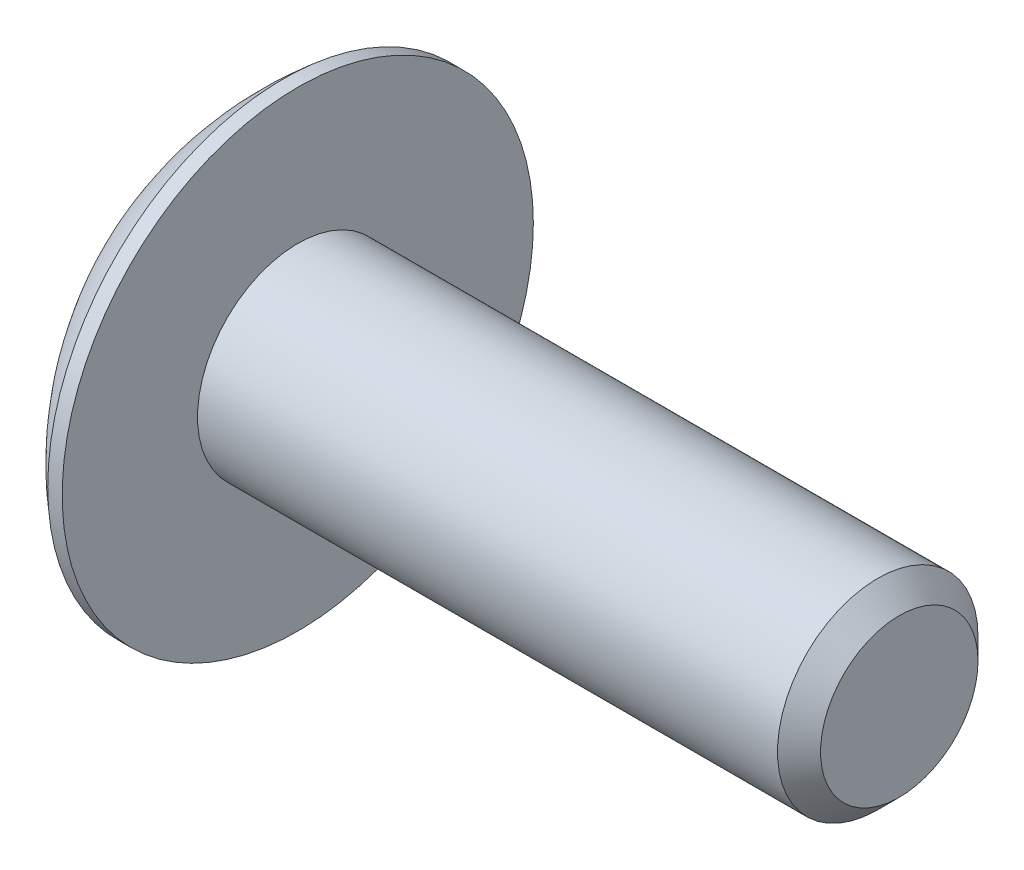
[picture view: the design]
ISO-10303-21;
HEADER;
FILE_DESCRIPTION(('STEP AP214'),'2;1');
FILE_NAME('part.step','',(''),(''),'','','');
FILE_SCHEMA(('AUTOMOTIVE_DESIGN { 1 0 10303 214 1 1 1 1 }'));
ENDSEC;
DATA;
#1=APPLICATION_CONTEXT('core data for automotive mechanical design processes');
#2=APPLICATION_PROTOCOL_DEFINITION('international standard','automotive_design',2000,#1);
#3=PRODUCT_CONTEXT('',#1,'mechanical');
#4=PRODUCT('Part','Part','',(#3));
#5=PRODUCT_RELATED_PRODUCT_CATEGORY('part','',(#4));
#6=PRODUCT_DEFINITION_FORMATION('','',#4);
#7=PRODUCT_DEFINITION_CONTEXT('part definition',#1,'design');
#8=PRODUCT_DEFINITION('design','',#6,#7);
#9=PRODUCT_DEFINITION_SHAPE('','',#8);
#10=(LENGTH_UNIT() NAMED_UNIT(*) SI_UNIT(.MILLI.,.METRE.));
#11=(NAMED_UNIT(*) PLANE_ANGLE_UNIT() SI_UNIT($,.RADIAN.));
#12=(NAMED_UNIT(*) SI_UNIT($,.STERADIAN.) SOLID_ANGLE_UNIT());
#13=UNCERTAINTY_MEASURE_WITH_UNIT(LENGTH_MEASURE(1.E-05),#10,'distance_accuracy_value','');
#14=(GEOMETRIC_REPRESENTATION_CONTEXT(3) GLOBAL_UNCERTAINTY_ASSIGNED_CONTEXT((#13)) GLOBAL_UNIT_ASSIGNED_CONTEXT((#10,
#11,#12)) REPRESENTATION_CONTEXT('',''));
#15=CARTESIAN_POINT('',(0.,0.,0.));
#16=DIRECTION('',(0.,0.,1.));
#17=DIRECTION('',(1.,0.,0.));
#18=AXIS2_PLACEMENT_3D('',#15,#16,#17);
#19=CARTESIAN_POINT('',(3.60000000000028,-1.29236898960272E-13,0.));
#20=DIRECTION('',(1.,0.,0.));
#21=DIRECTION('',(0.,1.,0.));
#22=AXIS2_PLACEMENT_3D('',#19,#20,#21);
#23=SPHERICAL_SURFACE('',#22,6.10000000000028);
#24=CARTESIAN_POINT('',(-0.288444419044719,0.,0.));
#25=DIRECTION('',(1.,0.,0.));
#26=DIRECTION('',(0.,0.,-1.));
#27=AXIS2_PLACEMENT_3D('',#24,#25,#26);
#28=CIRCLE('',#27,4.7);
#29=CARTESIAN_POINT('',(-0.288444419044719,0.,-4.7));
#30=VERTEX_POINT('',#29);
#31=EDGE_CURVE('E5',#30,#30,#28,.T.);
#32=ORIENTED_EDGE('',*,*,#31,.F.);
#33=EDGE_LOOP('',(#32));
#34=FACE_BOUND('',#33,.T.);
#35=CARTESIAN_POINT('',(-2.26198297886,0.626666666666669,1.5666666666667));
#36=CARTESIAN_POINT('',(-2.25890939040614,0.626667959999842,1.5781665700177));
#37=CARTESIAN_POINT('',(-2.25580100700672,0.626678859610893,1.58965715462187));
#38=CARTESIAN_POINT('',(-2.2494064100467,0.626709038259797,1.61301958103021));
#39=CARTESIAN_POINT('',(-2.24611777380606,0.626728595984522,1.62489075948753));
#40=CARTESIAN_POINT('',(-2.23937890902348,0.626764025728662,1.64893324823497));
#41=CARTESIAN_POINT('',(-2.23592671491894,0.626779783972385,1.66110400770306));
#42=CARTESIAN_POINT('',(-2.22887838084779,0.626801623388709,1.68566395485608));
#43=CARTESIAN_POINT('',(-2.22528074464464,0.626807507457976,1.698052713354));
#44=CARTESIAN_POINT('',(-2.2179609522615,0.626807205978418,1.72296657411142));
#45=CARTESIAN_POINT('',(-2.21423778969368,0.626800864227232,1.73549138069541));
#46=CARTESIAN_POINT('',(-2.20668807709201,0.626778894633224,1.76059497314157));
#47=CARTESIAN_POINT('',(-2.20286102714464,0.626763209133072,1.77317360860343));
#48=CARTESIAN_POINT('',(-2.19512675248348,0.626727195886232,1.7983024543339));
#49=CARTESIAN_POINT('',(-2.19121954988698,0.626706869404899,1.81085267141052));
#50=CARTESIAN_POINT('',(-2.18334912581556,0.626679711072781,1.8358420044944));
#51=CARTESIAN_POINT('',(-2.17938646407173,0.626672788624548,1.84828129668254));
#52=CARTESIAN_POINT('',(-2.17144141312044,0.626660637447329,1.87294574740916));
#53=CARTESIAN_POINT('',(-2.16746023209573,0.626655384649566,1.88517129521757));
#54=CARTESIAN_POINT('',(-2.15948191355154,0.626632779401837,1.90941347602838));
#55=CARTESIAN_POINT('',(-2.15548591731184,0.626615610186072,1.92143048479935));
#56=CARTESIAN_POINT('',(-2.1474531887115,0.626585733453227,1.94533538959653));
#57=CARTESIAN_POINT('',(-2.14341710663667,0.626572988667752,1.95722350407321));
#58=CARTESIAN_POINT('',(-2.13527849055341,0.62655544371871,1.98095075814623));
#59=CARTESIAN_POINT('',(-2.13117610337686,0.626550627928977,1.99278994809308));
#60=CARTESIAN_POINT('',(-2.12287713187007,0.626551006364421,2.01649936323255));
#61=CARTESIAN_POINT('',(-2.11868018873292,0.626556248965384,2.02836946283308));
#62=CARTESIAN_POINT('',(-2.1101626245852,0.626574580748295,2.05222057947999));
#63=CARTESIAN_POINT('',(-2.1058411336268,0.62658776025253,2.06420128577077));
#64=CARTESIAN_POINT('',(-2.0970431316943,0.626616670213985,2.08835324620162));
#65=CARTESIAN_POINT('',(-2.09256523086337,0.626632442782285,2.10052399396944));
#66=CARTESIAN_POINT('',(-2.08342122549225,0.626657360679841,2.12513535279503));
#67=CARTESIAN_POINT('',(-2.07875319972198,0.62666633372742,2.13757525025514));
#68=CARTESIAN_POINT('',(-2.07404519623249,0.62666666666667,2.15));
#69=B_SPLINE_CURVE_WITH_KNOTS('',3,(#35,#36,#37,#38,#39,#40,#41,#42,#43,#44,#45,#46,#47,#48,#49,
#50,#51,#52,#53,#54,#55,#56,#57,#58,#59,#60,#61,#62,#63,#64,#65,#66,#67,#68),.UNSPECIFIED.,.F.,
.F.,(4,2,2,2,2,2,2,2,2,2,2,2,2,2,2,2,4),(0.,0.0357105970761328,0.0726652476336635,
0.110617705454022,0.149319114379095,0.188518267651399,0.227961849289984,0.267394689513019,
0.306560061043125,0.345132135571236,0.383123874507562,0.420787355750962,0.45837652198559,
0.496146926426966,0.534355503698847,0.573260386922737,0.613120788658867),.UNSPECIFIED.);
#70=CARTESIAN_POINT('',(-2.26198297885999,0.62666666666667,1.5666666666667));
#71=VERTEX_POINT('',#70);
#72=CARTESIAN_POINT('',(-2.07404519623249,0.62666666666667,2.15));
#73=VERTEX_POINT('',#72);
#74=EDGE_CURVE('E8',#71,#73,#69,.T.);
#75=ORIENTED_EDGE('',*,*,#74,.T.);
#76=CARTESIAN_POINT('',(-2.07404519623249,0.626666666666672,2.15));
#77=CARTESIAN_POINT('',(-2.07704980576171,0.599465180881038,2.14999909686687));
#78=CARTESIAN_POINT('',(-2.07986503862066,0.57224267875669,2.14998150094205));
#79=CARTESIAN_POINT('',(-2.08506116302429,0.51825623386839,2.14993301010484));
#80=CARTESIAN_POINT('',(-2.08744902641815,0.491492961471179,2.14990236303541));
#81=CARTESIAN_POINT('',(-2.09181031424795,0.438353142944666,2.14984684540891));
#82=CARTESIAN_POINT('',(-2.09378962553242,0.411977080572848,2.14982189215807));
#83=CARTESIAN_POINT('',(-2.09735237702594,0.359540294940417,2.14978796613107));
#84=CARTESIAN_POINT('',(-2.09894059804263,0.333479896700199,2.14977879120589));
#85=CARTESIAN_POINT('',(-2.1017378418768,0.281603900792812,2.14977968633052));
#86=CARTESIAN_POINT('',(-2.10295054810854,0.255788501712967,2.1497895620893));
#87=CARTESIAN_POINT('',(-2.10501180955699,0.204333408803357,2.14982468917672));
#88=CARTESIAN_POINT('',(-2.10586297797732,0.178693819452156,2.14984982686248));
#89=CARTESIAN_POINT('',(-2.10721463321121,0.127523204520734,2.14990488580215));
#90=CARTESIAN_POINT('',(-2.10771671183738,0.101992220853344,2.14993478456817));
#91=CARTESIAN_POINT('',(-2.10838218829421,0.0509741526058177,2.14998233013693));
#92=CARTESIAN_POINT('',(-2.10854622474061,0.025487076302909,2.15));
#93=CARTESIAN_POINT('',(-2.10854622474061,-0.0254870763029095,2.15));
#94=CARTESIAN_POINT('',(-2.10838218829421,-0.0509741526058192,2.14998233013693));
#95=CARTESIAN_POINT('',(-2.10771671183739,-0.101992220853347,2.14993478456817));
#96=CARTESIAN_POINT('',(-2.10721463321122,-0.127523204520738,2.14990488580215));
#97=CARTESIAN_POINT('',(-2.10586297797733,-0.17869381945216,2.14984982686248));
#98=CARTESIAN_POINT('',(-2.10501180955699,-0.204333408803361,2.14982468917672));
#99=CARTESIAN_POINT('',(-2.10295054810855,-0.255788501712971,2.1497895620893));
#100=CARTESIAN_POINT('',(-2.10173784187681,-0.281603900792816,2.14977968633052));
#101=CARTESIAN_POINT('',(-2.09894059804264,-0.333479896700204,2.14977879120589));
#102=CARTESIAN_POINT('',(-2.09735237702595,-0.359540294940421,2.14978796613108));
#103=CARTESIAN_POINT('',(-2.09378962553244,-0.411977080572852,2.14982189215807));
#104=CARTESIAN_POINT('',(-2.09181031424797,-0.438353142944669,2.14984684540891));
#105=CARTESIAN_POINT('',(-2.08744902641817,-0.491492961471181,2.14990236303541));
#106=CARTESIAN_POINT('',(-2.08506116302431,-0.518256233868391,2.14993301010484));
#107=CARTESIAN_POINT('',(-2.07986503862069,-0.57224267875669,2.14998150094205));
#108=CARTESIAN_POINT('',(-2.07704980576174,-0.599465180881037,2.14999909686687));
#109=CARTESIAN_POINT('',(-2.07404519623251,-0.626666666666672,2.15));
#110=B_SPLINE_CURVE_WITH_KNOTS('',3,(#76,#77,#78,#79,#80,#81,#82,#83,#84,#85,#86,#87,#88,#89,
#90,#91,#92,#93,#94,#95,#96,#97,#98,#99,#100,#101,#102,#103,#104,#105,#106,#107,#108,#109),
.UNSPECIFIED.,.F.,.F.,(4,2,2,2,2,2,2,2,2,2,2,2,2,2,2,2,4),(0.,0.0821002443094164,
0.162706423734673,0.242054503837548,0.320378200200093,0.397907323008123,0.47486611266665,
0.551471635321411,0.62793230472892,0.704392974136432,0.780998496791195,0.857957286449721,
0.935486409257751,1.0138101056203,1.09315818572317,1.17376436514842,1.25586460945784),.UNSPECIFIED.);
#111=CARTESIAN_POINT('',(-2.07404519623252,-0.62666666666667,2.15));
#112=VERTEX_POINT('',#111);
#113=EDGE_CURVE('E23',#73,#112,#110,.T.);
#114=ORIENTED_EDGE('',*,*,#113,.T.);
#115=CARTESIAN_POINT('',(-2.07404519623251,-0.626666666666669,2.15));
#116=CARTESIAN_POINT('',(-2.07875319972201,-0.62666633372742,2.13757525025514));
#117=CARTESIAN_POINT('',(-2.08342122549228,-0.626657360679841,2.12513535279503));
#118=CARTESIAN_POINT('',(-2.0925652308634,-0.626632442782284,2.10052399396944));
#119=CARTESIAN_POINT('',(-2.09704313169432,-0.626616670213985,2.08835324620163));
#120=CARTESIAN_POINT('',(-2.10584113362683,-0.626587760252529,2.06420128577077));
#121=CARTESIAN_POINT('',(-2.11016262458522,-0.626574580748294,2.05222057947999));
#122=CARTESIAN_POINT('',(-2.11868018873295,-0.626556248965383,2.02836946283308));
#123=CARTESIAN_POINT('',(-2.1228771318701,-0.62655100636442,2.01649936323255));
#124=CARTESIAN_POINT('',(-2.13117610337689,-0.626550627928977,1.99278994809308));
#125=CARTESIAN_POINT('',(-2.13527849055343,-0.62655544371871,1.98095075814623));
#126=CARTESIAN_POINT('',(-2.1434171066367,-0.626572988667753,1.95722350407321));
#127=CARTESIAN_POINT('',(-2.14745318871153,-0.626585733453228,1.94533538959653));
#128=CARTESIAN_POINT('',(-2.15548591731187,-0.626615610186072,1.92143048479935));
#129=CARTESIAN_POINT('',(-2.15948191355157,-0.626632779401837,1.90941347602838));
#130=CARTESIAN_POINT('',(-2.16746023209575,-0.626655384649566,1.88517129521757));
#131=CARTESIAN_POINT('',(-2.17144141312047,-0.626660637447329,1.87294574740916));
#132=CARTESIAN_POINT('',(-2.17938646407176,-0.626672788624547,1.84828129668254));
#133=CARTESIAN_POINT('',(-2.18334912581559,-0.626679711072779,1.8358420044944));
#134=CARTESIAN_POINT('',(-2.19121954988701,-0.626706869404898,1.81085267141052));
#135=CARTESIAN_POINT('',(-2.1951267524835,-0.626727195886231,1.7983024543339));
#136=CARTESIAN_POINT('',(-2.20286102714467,-0.626763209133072,1.77317360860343));
#137=CARTESIAN_POINT('',(-2.20668807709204,-0.626778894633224,1.76059497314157));
#138=CARTESIAN_POINT('',(-2.21423778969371,-0.626800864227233,1.73549138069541));
#139=CARTESIAN_POINT('',(-2.21796095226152,-0.626807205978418,1.72296657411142));
#140=CARTESIAN_POINT('',(-2.22528074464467,-0.626807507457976,1.69805271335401));
#141=CARTESIAN_POINT('',(-2.22887838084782,-0.626801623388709,1.68566395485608));
#142=CARTESIAN_POINT('',(-2.23592671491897,-0.626779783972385,1.66110400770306));
#143=CARTESIAN_POINT('',(-2.2393789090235,-0.626764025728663,1.64893324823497));
#144=CARTESIAN_POINT('',(-2.24611777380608,-0.626728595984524,1.62489075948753));
#145=CARTESIAN_POINT('',(-2.24940641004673,-0.626709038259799,1.61301958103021));
#146=CARTESIAN_POINT('',(-2.25580100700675,-0.626678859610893,1.58965715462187));
#147=CARTESIAN_POINT('',(-2.25890939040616,-0.626667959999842,1.5781665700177));
#148=CARTESIAN_POINT('',(-2.26198297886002,-0.62666666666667,1.5666666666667));
#149=B_SPLINE_CURVE_WITH_KNOTS('',3,(#115,#116,#117,#118,#119,#120,#121,#122,#123,#124,#125,
#126,#127,#128,#129,#130,#131,#132,#133,#134,#135,#136,#137,#138,#139,#140,#141,#142,#143,#144,
#145,#146,#147,#148),.UNSPECIFIED.,.F.,.F.,(4,2,2,2,2,2,2,2,2,2,2,2,2,2,2,2,4),(0.,
0.03986040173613,0.0787652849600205,0.116973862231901,0.154744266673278,0.192333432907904,
0.229996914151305,0.267988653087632,0.306560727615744,0.345726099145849,0.385158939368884,
0.424602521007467,0.463801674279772,0.502503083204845,0.540455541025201,0.577410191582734,
0.613120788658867),.UNSPECIFIED.);
#150=CARTESIAN_POINT('',(-2.26198297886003,-0.62666666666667,1.5666666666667));
#151=VERTEX_POINT('',#150);
#152=EDGE_CURVE('E37',#112,#151,#149,.T.);
#153=ORIENTED_EDGE('',*,*,#152,.T.);
#154=CARTESIAN_POINT('',(-2.26198297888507,-1.56666666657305,0.626666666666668));
#155=CARTESIAN_POINT('',(-2.26520019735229,-1.55462889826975,0.626666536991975));
#156=CARTESIAN_POINT('',(-2.26835697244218,-1.54257482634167,0.626897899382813));
#157=CARTESIAN_POINT('',(-2.27454382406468,-1.51845661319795,0.627826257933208));
#158=CARTESIAN_POINT('',(-2.27757394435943,-1.50639247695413,0.628523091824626));
#159=CARTESIAN_POINT('',(-2.28350314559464,-1.4822714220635,0.630384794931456));
#160=CARTESIAN_POINT('',(-2.28640226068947,-1.47021450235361,0.631549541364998));
#161=CARTESIAN_POINT('',(-2.29206511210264,-1.44612548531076,0.634348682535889));
#162=CARTESIAN_POINT('',(-2.29482887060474,-1.43409338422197,0.635983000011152));
#163=CARTESIAN_POINT('',(-2.30021667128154,-1.41007177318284,0.639722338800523));
#164=CARTESIAN_POINT('',(-2.30284072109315,-1.39808226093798,0.641827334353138));
#165=CARTESIAN_POINT('',(-2.30794477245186,-1.37416378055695,0.64650844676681));
#166=CARTESIAN_POINT('',(-2.31042476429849,-1.36223481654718,0.649084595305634));
#167=CARTESIAN_POINT('',(-2.31523635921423,-1.33845553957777,0.654707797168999));
#168=CARTESIAN_POINT('',(-2.31756793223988,-1.32660524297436,0.657754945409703));
#169=CARTESIAN_POINT('',(-2.32207839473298,-1.30300155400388,0.664319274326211));
#170=CARTESIAN_POINT('',(-2.3242572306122,-1.2912481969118,0.667836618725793));
#171=CARTESIAN_POINT('',(-2.32845717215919,-1.26786005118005,0.675338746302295));
#172=CARTESIAN_POINT('',(-2.33047824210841,-1.2562252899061,0.679323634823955));
#173=CARTESIAN_POINT('',(-2.33435678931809,-1.23310506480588,0.687753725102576));
#174=CARTESIAN_POINT('',(-2.33621437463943,-1.22161950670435,0.692198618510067));
#175=CARTESIAN_POINT('',(-2.33976346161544,-1.19881668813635,0.701543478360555));
#176=CARTESIAN_POINT('',(-2.34145505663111,-1.18749933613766,0.706443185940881));
#177=CARTESIAN_POINT('',(-2.34466971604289,-1.16505055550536,0.716692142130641));
#178=CARTESIAN_POINT('',(-2.34619283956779,-1.15391906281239,0.722041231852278));
#179=CARTESIAN_POINT('',(-2.34906816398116,-1.13185950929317,0.733182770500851));
#180=CARTESIAN_POINT('',(-2.35042038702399,-1.12093142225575,0.738975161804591));
#181=CARTESIAN_POINT('',(-2.35295150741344,-1.09929603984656,0.750996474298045));
#182=CARTESIAN_POINT('',(-2.35413038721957,-1.08858876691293,0.757225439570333));
#183=CARTESIAN_POINT('',(-2.35631242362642,-1.06741220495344,0.770112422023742));
#184=CARTESIAN_POINT('',(-2.3573155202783,-1.05694299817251,0.776770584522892));
#185=CARTESIAN_POINT('',(-2.35914359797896,-1.03625957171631,0.790507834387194));
#186=CARTESIAN_POINT('',(-2.35996847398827,-1.02604550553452,0.797587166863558));
#187=CARTESIAN_POINT('',(-2.3614376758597,-1.00588959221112,0.81215766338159));
#188=CARTESIAN_POINT('',(-2.36208185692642,-0.995947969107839,0.819649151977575));
#189=CARTESIAN_POINT('',(-2.36318662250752,-0.976365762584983,0.835024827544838));
#190=CARTESIAN_POINT('',(-2.36364724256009,-0.96672512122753,0.842908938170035));
#191=CARTESIAN_POINT('',(-2.36438476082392,-0.947765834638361,0.859053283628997));
#192=CARTESIAN_POINT('',(-2.36466175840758,-0.938447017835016,0.86731331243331));
#193=CARTESIAN_POINT('',(-2.36503230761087,-0.92014596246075,0.884196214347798));
#194=CARTESIAN_POINT('',(-2.3651259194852,-0.911163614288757,0.892818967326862));
#195=CARTESIAN_POINT('',(-2.36513000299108,-0.893549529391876,0.910413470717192));
#196=CARTESIAN_POINT('',(-2.36504049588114,-0.88491775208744,0.919385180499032));
#197=CARTESIAN_POINT('',(-2.36467864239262,-0.868018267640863,0.93766320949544));
#198=CARTESIAN_POINT('',(-2.36440627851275,-0.859750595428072,0.946969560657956));
#199=CARTESIAN_POINT('',(-2.36367900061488,-0.843592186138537,0.96590196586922));
#200=CARTESIAN_POINT('',(-2.36322403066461,-0.835701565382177,0.975528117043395));
#201=CARTESIAN_POINT('',(-2.36213188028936,-0.820309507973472,0.995084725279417));
#202=CARTESIAN_POINT('',(-2.36149460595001,-0.812808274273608,1.0050153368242));
#203=CARTESIAN_POINT('',(-2.36003800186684,-0.798206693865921,1.02516488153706));
#204=CARTESIAN_POINT('',(-2.3592185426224,-0.791106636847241,1.0353840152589));
#205=CARTESIAN_POINT('',(-2.35739943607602,-0.777325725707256,1.05608322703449));
#206=CARTESIAN_POINT('',(-2.35639981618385,-0.770644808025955,1.06656326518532));
#207=CARTESIAN_POINT('',(-2.35422388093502,-0.757715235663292,1.08775998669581));
#208=CARTESIAN_POINT('',(-2.35304767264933,-0.751466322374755,1.09847652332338));
#209=CARTESIAN_POINT('',(-2.35052125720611,-0.73940756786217,1.12012899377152));
#210=CARTESIAN_POINT('',(-2.34917110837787,-0.733597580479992,1.13106485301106));
#211=CARTESIAN_POINT('',(-2.34629960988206,-0.722422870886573,1.15313863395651));
#212=CARTESIAN_POINT('',(-2.34477827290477,-0.71705811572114,1.16427654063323));
#213=CARTESIAN_POINT('',(-2.34156716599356,-0.706779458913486,1.18673700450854));
#214=CARTESIAN_POINT('',(-2.33987736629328,-0.70186563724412,1.19805959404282));
#215=CARTESIAN_POINT('',(-2.33633210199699,-0.692493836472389,1.22087195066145));
#216=CARTESIAN_POINT('',(-2.3344765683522,-0.688036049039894,1.23236178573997));
#217=CARTESIAN_POINT('',(-2.33060261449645,-0.679580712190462,1.25549111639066));
#218=CARTESIAN_POINT('',(-2.32858408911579,-0.675583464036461,1.26713070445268));
#219=CARTESIAN_POINT('',(-2.32438689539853,-0.668053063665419,1.29054183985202));
#220=CARTESIAN_POINT('',(-2.32220809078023,-0.664520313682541,1.30231349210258));
#221=CARTESIAN_POINT('',(-2.31769491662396,-0.657924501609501,1.32596264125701));
#222=CARTESIAN_POINT('',(-2.31536049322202,-0.654861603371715,1.33784017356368));
#223=CARTESIAN_POINT('',(-2.31054161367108,-0.649208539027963,1.36167732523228));
#224=CARTESIAN_POINT('',(-2.30805715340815,-0.646618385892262,1.37363694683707));
#225=CARTESIAN_POINT('',(-2.30294285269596,-0.641911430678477,1.39761906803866));
#226=CARTESIAN_POINT('',(-2.30031300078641,-0.639794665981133,1.40964157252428));
#227=CARTESIAN_POINT('',(-2.29491260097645,-0.636034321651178,1.43373037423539));
#228=CARTESIAN_POINT('',(-2.29214203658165,-0.634390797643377,1.44579667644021));
#229=CARTESIAN_POINT('',(-2.28646488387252,-0.631575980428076,1.46995414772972));
#230=CARTESIAN_POINT('',(-2.2835582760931,-0.630404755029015,1.48204532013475));
#231=CARTESIAN_POINT('',(-2.27761371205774,-0.62853287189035,1.50623376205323));
#232=CARTESIAN_POINT('',(-2.27457573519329,-0.627832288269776,1.51833103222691));
#233=CARTESIAN_POINT('',(-2.26837309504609,-0.62689908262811,1.54251322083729));
#234=CARTESIAN_POINT('',(-2.26520841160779,-0.626666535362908,1.55459813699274));
#235=CARTESIAN_POINT('',(-2.2619829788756,-0.626666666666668,1.5666666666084));
#236=B_SPLINE_CURVE_WITH_KNOTS('',3,(#154,#155,#156,#157,#158,#159,#160,#161,#162,#163,#164,
#165,#166,#167,#168,#169,#170,#171,#172,#173,#174,#175,#176,#177,#178,#179,#180,#181,#182,#183,
#184,#185,#186,#187,#188,#189,#190,#191,#192,#193,#194,#195,#196,#197,#198,#199,#200,#201,#202,
#203,#204,#205,#206,#207,#208,#209,#210,#211,#212,#213,#214,#215,#216,#217,#218,#219,#220,#221,
#222,#223,#224,#225,#226,#227,#228,#229,#230,#231,#232,#233,#234,#235),.UNSPECIFIED.,.F.,.F.,(4,
2,2,2,2,2,2,2,2,2,2,2,2,2,2,2,2,2,2,2,2,2,2,2,2,2,2,2,2,2,2,2,2,2,2,2,2,2,2,2,4),(0.,
0.0373787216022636,0.0747444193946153,0.112100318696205,0.1494500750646,0.186797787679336,
0.224148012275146,0.261505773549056,0.29887657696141,0.336255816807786,0.373610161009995,
0.410943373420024,0.448263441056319,0.485578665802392,0.522897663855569,0.560229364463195,
0.597583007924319,0.634966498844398,0.672342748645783,0.709698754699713,0.747042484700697,
0.78438187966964,0.821724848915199,0.859079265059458,0.896452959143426,0.933853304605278,
0.971247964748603,1.00862004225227,1.04597961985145,1.08333642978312,1.12069985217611,
1.15807891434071,1.19548229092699,1.23291784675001,1.27036642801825,1.30781603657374,
1.34526860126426,1.38272556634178,1.42018790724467,1.45765614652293,1.49513036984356),.UNSPECIFIED.);
#237=CARTESIAN_POINT('',(-2.26198297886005,-1.5666666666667,0.62666666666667));
#238=VERTEX_POINT('',#237);
#239=EDGE_CURVE('E51',#238,#151,#236,.T.);
#240=ORIENTED_EDGE('',*,*,#239,.F.);
#241=CARTESIAN_POINT('',(-2.26198297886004,-1.5666666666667,0.626666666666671));
#242=CARTESIAN_POINT('',(-2.25890939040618,-1.5781665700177,0.626667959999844));
#243=CARTESIAN_POINT('',(-2.25580100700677,-1.58965715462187,0.626678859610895));
#244=CARTESIAN_POINT('',(-2.24940641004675,-1.61301958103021,0.626709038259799));
#245=CARTESIAN_POINT('',(-2.24611777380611,-1.62489075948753,0.626728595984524));
#246=CARTESIAN_POINT('',(-2.23937890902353,-1.64893324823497,0.626764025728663));
#247=CARTESIAN_POINT('',(-2.23592671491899,-1.66110400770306,0.626779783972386));
#248=CARTESIAN_POINT('',(-2.22887838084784,-1.68566395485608,0.62680162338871));
#249=CARTESIAN_POINT('',(-2.22528074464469,-1.698052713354,0.626807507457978));
#250=CARTESIAN_POINT('',(-2.21796095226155,-1.72296657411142,0.626807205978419));
#251=CARTESIAN_POINT('',(-2.21423778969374,-1.73549138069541,0.626800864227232));
#252=CARTESIAN_POINT('',(-2.20668807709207,-1.76059497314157,0.626778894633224));
#253=CARTESIAN_POINT('',(-2.20286102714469,-1.77317360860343,0.626763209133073));
#254=CARTESIAN_POINT('',(-2.19512675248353,-1.7983024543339,0.626727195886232));
#255=CARTESIAN_POINT('',(-2.19121954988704,-1.81085267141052,0.626706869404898));
#256=CARTESIAN_POINT('',(-2.18334912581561,-1.8358420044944,0.626679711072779));
#257=CARTESIAN_POINT('',(-2.17938646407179,-1.84828129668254,0.626672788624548));
#258=CARTESIAN_POINT('',(-2.1714414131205,-1.87294574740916,0.62666063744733));
#259=CARTESIAN_POINT('',(-2.16746023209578,-1.88517129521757,0.626655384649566));
#260=CARTESIAN_POINT('',(-2.1594819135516,-1.90941347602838,0.626632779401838));
#261=CARTESIAN_POINT('',(-2.1554859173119,-1.92143048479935,0.626615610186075));
#262=CARTESIAN_POINT('',(-2.14745318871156,-1.94533538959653,0.62658573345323));
#263=CARTESIAN_POINT('',(-2.14341710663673,-1.95722350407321,0.626572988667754));
#264=CARTESIAN_POINT('',(-2.13527849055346,-1.98095075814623,0.62655544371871));
#265=CARTESIAN_POINT('',(-2.13117610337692,-1.99278994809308,0.626550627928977));
#266=CARTESIAN_POINT('',(-2.12287713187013,-2.01649936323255,0.626551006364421));
#267=CARTESIAN_POINT('',(-2.11868018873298,-2.02836946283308,0.626556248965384));
#268=CARTESIAN_POINT('',(-2.11016262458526,-2.05222057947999,0.626574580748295));
#269=CARTESIAN_POINT('',(-2.10584113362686,-2.06420128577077,0.62658776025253));
#270=CARTESIAN_POINT('',(-2.09704313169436,-2.08835324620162,0.626616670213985));
#271=CARTESIAN_POINT('',(-2.09256523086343,-2.10052399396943,0.626632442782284));
#272=CARTESIAN_POINT('',(-2.08342122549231,-2.12513535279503,0.626657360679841));
#273=CARTESIAN_POINT('',(-2.07875319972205,-2.13757525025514,0.62666633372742));
#274=CARTESIAN_POINT('',(-2.07404519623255,-2.15,0.62666666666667));
#275=B_SPLINE_CURVE_WITH_KNOTS('',3,(#241,#242,#243,#244,#245,#246,#247,#248,#249,#250,#251,
#252,#253,#254,#255,#256,#257,#258,#259,#260,#261,#262,#263,#264,#265,#266,#267,#268,#269,#270,
#271,#272,#273,#274),.UNSPECIFIED.,.F.,.F.,(4,2,2,2,2,2,2,2,2,2,2,2,2,2,2,2,4),(0.,
0.0357105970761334,0.0726652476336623,0.110617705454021,0.149319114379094,0.188518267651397,
0.227961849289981,0.267394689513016,0.306560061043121,0.345132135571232,0.383123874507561,
0.420787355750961,0.458376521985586,0.49614692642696,0.534355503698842,0.573260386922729,
0.613120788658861),.UNSPECIFIED.);
#276=CARTESIAN_POINT('',(-2.07404519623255,-2.15,0.62666666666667));
#277=VERTEX_POINT('',#276);
#278=EDGE_CURVE('E65',#238,#277,#275,.T.);
#279=ORIENTED_EDGE('',*,*,#278,.T.);
#280=CARTESIAN_POINT('',(-2.07404519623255,-2.15,0.626666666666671));
#281=CARTESIAN_POINT('',(-2.07704980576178,-2.14999909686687,0.599465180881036));
#282=CARTESIAN_POINT('',(-2.07986503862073,-2.14998150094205,0.572242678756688));
#283=CARTESIAN_POINT('',(-2.08506116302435,-2.14993301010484,0.518256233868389));
#284=CARTESIAN_POINT('',(-2.08744902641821,-2.14990236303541,0.49149296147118));
#285=CARTESIAN_POINT('',(-2.09181031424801,-2.14984684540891,0.438353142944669));
#286=CARTESIAN_POINT('',(-2.09378962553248,-2.14982189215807,0.411977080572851));
#287=CARTESIAN_POINT('',(-2.09735237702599,-2.14978796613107,0.359540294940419));
#288=CARTESIAN_POINT('',(-2.09894059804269,-2.14977879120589,0.3334798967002));
#289=CARTESIAN_POINT('',(-2.10173784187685,-2.14977968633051,0.281603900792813));
#290=CARTESIAN_POINT('',(-2.10295054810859,-2.1497895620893,0.25578850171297));
#291=CARTESIAN_POINT('',(-2.10501180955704,-2.14982468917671,0.204333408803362));
#292=CARTESIAN_POINT('',(-2.10586297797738,-2.14984982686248,0.178693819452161));
#293=CARTESIAN_POINT('',(-2.10721463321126,-2.14990488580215,0.127523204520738));
#294=CARTESIAN_POINT('',(-2.10771671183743,-2.14993478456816,0.101992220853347));
#295=CARTESIAN_POINT('',(-2.10838218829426,-2.14998233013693,0.0509741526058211));
#296=CARTESIAN_POINT('',(-2.10854622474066,-2.15,0.0254870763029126));
#297=CARTESIAN_POINT('',(-2.10854622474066,-2.15,-0.0254870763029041));
#298=CARTESIAN_POINT('',(-2.10838218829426,-2.14998233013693,-0.0509741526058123));
#299=CARTESIAN_POINT('',(-2.10771671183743,-2.14993478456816,-0.101992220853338));
#300=CARTESIAN_POINT('',(-2.10721463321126,-2.14990488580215,-0.127523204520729));
#301=CARTESIAN_POINT('',(-2.10586297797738,-2.14984982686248,-0.17869381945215));
#302=CARTESIAN_POINT('',(-2.10501180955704,-2.14982468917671,-0.204333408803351));
#303=CARTESIAN_POINT('',(-2.10295054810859,-2.1497895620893,-0.25578850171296));
#304=CARTESIAN_POINT('',(-2.10173784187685,-2.14977968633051,-0.281603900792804));
#305=CARTESIAN_POINT('',(-2.09894059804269,-2.14977879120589,-0.333479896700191));
#306=CARTESIAN_POINT('',(-2.097352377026,-2.14978796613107,-0.359540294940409));
#307=CARTESIAN_POINT('',(-2.09378962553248,-2.14982189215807,-0.41197708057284));
#308=CARTESIAN_POINT('',(-2.09181031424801,-2.1498468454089,-0.438353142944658));
#309=CARTESIAN_POINT('',(-2.08744902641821,-2.1499023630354,-0.491492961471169));
#310=CARTESIAN_POINT('',(-2.08506116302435,-2.14993301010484,-0.518256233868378));
#311=CARTESIAN_POINT('',(-2.07986503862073,-2.14998150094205,-0.572242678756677));
#312=CARTESIAN_POINT('',(-2.07704980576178,-2.14999909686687,-0.599465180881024));
#313=CARTESIAN_POINT('',(-2.07404519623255,-2.15,-0.626666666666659));
#314=B_SPLINE_CURVE_WITH_KNOTS('',3,(#280,#281,#282,#283,#284,#285,#286,#287,#288,#289,#290,
#291,#292,#293,#294,#295,#296,#297,#298,#299,#300,#301,#302,#303,#304,#305,#306,#307,#308,#309,
#310,#311,#312,#313),.UNSPECIFIED.,.F.,.F.,(4,2,2,2,2,2,2,2,2,2,2,2,2,2,2,2,4),(0.,
0.082100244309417,0.162706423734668,0.242054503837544,0.320378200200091,0.397907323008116,
0.474866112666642,0.551471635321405,0.627932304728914,0.704392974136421,0.780998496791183,
0.857957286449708,0.935486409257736,1.01381010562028,1.09315818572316,1.17376436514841,
1.25586460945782),.UNSPECIFIED.);
#315=CARTESIAN_POINT('',(-2.07404519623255,-2.15,-0.62666666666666));
#316=VERTEX_POINT('',#315);
#317=EDGE_CURVE('E79',#277,#316,#314,.T.);
#318=ORIENTED_EDGE('',*,*,#317,.T.);
#319=CARTESIAN_POINT('',(-2.07404519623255,-2.15,-0.626666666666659));
#320=CARTESIAN_POINT('',(-2.07875319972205,-2.13757525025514,-0.626666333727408));
#321=CARTESIAN_POINT('',(-2.08342122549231,-2.12513535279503,-0.626657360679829));
#322=CARTESIAN_POINT('',(-2.09256523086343,-2.10052399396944,-0.626632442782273));
#323=CARTESIAN_POINT('',(-2.09704313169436,-2.08835324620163,-0.626616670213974));
#324=CARTESIAN_POINT('',(-2.10584113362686,-2.06420128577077,-0.626587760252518));
#325=CARTESIAN_POINT('',(-2.11016262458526,-2.05222057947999,-0.626574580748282));
#326=CARTESIAN_POINT('',(-2.11868018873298,-2.02836946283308,-0.626556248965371));
#327=CARTESIAN_POINT('',(-2.12287713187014,-2.01649936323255,-0.626551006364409));
#328=CARTESIAN_POINT('',(-2.13117610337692,-1.99278994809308,-0.626550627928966));
#329=CARTESIAN_POINT('',(-2.13527849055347,-1.98095075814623,-0.626555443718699));
#330=CARTESIAN_POINT('',(-2.14341710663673,-1.95722350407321,-0.626572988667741));
#331=CARTESIAN_POINT('',(-2.14745318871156,-1.94533538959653,-0.626585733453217));
#332=CARTESIAN_POINT('',(-2.1554859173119,-1.92143048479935,-0.626615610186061));
#333=CARTESIAN_POINT('',(-2.1594819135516,-1.90941347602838,-0.626632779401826));
#334=CARTESIAN_POINT('',(-2.16746023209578,-1.88517129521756,-0.626655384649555));
#335=CARTESIAN_POINT('',(-2.1714414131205,-1.87294574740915,-0.626660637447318));
#336=CARTESIAN_POINT('',(-2.17938646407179,-1.84828129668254,-0.626672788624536));
#337=CARTESIAN_POINT('',(-2.18334912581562,-1.83584200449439,-0.626679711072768));
#338=CARTESIAN_POINT('',(-2.19121954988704,-1.81085267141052,-0.626706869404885));
#339=CARTESIAN_POINT('',(-2.19512675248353,-1.79830245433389,-0.626727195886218));
#340=CARTESIAN_POINT('',(-2.20286102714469,-1.77317360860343,-0.62676320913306));
#341=CARTESIAN_POINT('',(-2.20668807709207,-1.76059497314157,-0.626778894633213));
#342=CARTESIAN_POINT('',(-2.21423778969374,-1.7354913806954,-0.626800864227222));
#343=CARTESIAN_POINT('',(-2.21796095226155,-1.72296657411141,-0.626807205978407));
#344=CARTESIAN_POINT('',(-2.2252807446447,-1.698052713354,-0.626807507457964));
#345=CARTESIAN_POINT('',(-2.22887838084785,-1.68566395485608,-0.626801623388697));
#346=CARTESIAN_POINT('',(-2.23592671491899,-1.66110400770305,-0.626779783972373));
#347=CARTESIAN_POINT('',(-2.23937890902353,-1.64893324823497,-0.626764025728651));
#348=CARTESIAN_POINT('',(-2.24611777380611,-1.62489075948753,-0.626728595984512));
#349=CARTESIAN_POINT('',(-2.24940641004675,-1.61301958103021,-0.626709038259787));
#350=CARTESIAN_POINT('',(-2.25580100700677,-1.58965715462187,-0.626678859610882));
#351=CARTESIAN_POINT('',(-2.25890939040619,-1.5781665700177,-0.626667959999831));
#352=CARTESIAN_POINT('',(-2.26198297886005,-1.5666666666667,-0.626666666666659));
#353=B_SPLINE_CURVE_WITH_KNOTS('',3,(#319,#320,#321,#322,#323,#324,#325,#326,#327,#328,#329,
#330,#331,#332,#333,#334,#335,#336,#337,#338,#339,#340,#341,#342,#343,#344,#345,#346,#347,#348,
#349,#350,#351,#352),.UNSPECIFIED.,.F.,.F.,(4,2,2,2,2,2,2,2,2,2,2,2,2,2,2,2,4),(0.,
0.0398604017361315,0.0787652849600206,0.116973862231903,0.154744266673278,0.192333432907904,
0.229996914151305,0.267988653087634,0.306560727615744,0.34572609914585,0.385158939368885,
0.42460252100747,0.463801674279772,0.502503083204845,0.540455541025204,0.577410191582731,
0.613120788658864),.UNSPECIFIED.);
#354=CARTESIAN_POINT('',(-2.26198297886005,-1.5666666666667,-0.62666666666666));
#355=VERTEX_POINT('',#354);
#356=EDGE_CURVE('E93',#316,#355,#353,.T.);
#357=ORIENTED_EDGE('',*,*,#356,.T.);
#358=CARTESIAN_POINT('',(-2.26198297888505,-0.626666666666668,-1.56666666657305));
#359=CARTESIAN_POINT('',(-2.26520019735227,-0.626666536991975,-1.55462889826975));
#360=CARTESIAN_POINT('',(-2.26835697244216,-0.626897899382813,-1.54257482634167));
#361=CARTESIAN_POINT('',(-2.27454382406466,-0.627826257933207,-1.51845661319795));
#362=CARTESIAN_POINT('',(-2.27757394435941,-0.628523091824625,-1.50639247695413));
#363=CARTESIAN_POINT('',(-2.28350314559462,-0.630384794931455,-1.4822714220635));
#364=CARTESIAN_POINT('',(-2.28640226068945,-0.631549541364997,-1.47021450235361));
#365=CARTESIAN_POINT('',(-2.29206511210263,-0.634348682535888,-1.44612548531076));
#366=CARTESIAN_POINT('',(-2.29482887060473,-0.635983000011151,-1.43409338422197));
#367=CARTESIAN_POINT('',(-2.30021667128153,-0.639722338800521,-1.41007177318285));
#368=CARTESIAN_POINT('',(-2.30284072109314,-0.641827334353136,-1.39808226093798));
#369=CARTESIAN_POINT('',(-2.30794477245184,-0.646508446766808,-1.37416378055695));
#370=CARTESIAN_POINT('',(-2.31042476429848,-0.649084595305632,-1.36223481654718));
#371=CARTESIAN_POINT('',(-2.31523635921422,-0.654707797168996,-1.33845553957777));
#372=CARTESIAN_POINT('',(-2.31756793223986,-0.6577549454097,-1.32660524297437));
#373=CARTESIAN_POINT('',(-2.32207839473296,-0.664319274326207,-1.30300155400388));
#374=CARTESIAN_POINT('',(-2.32425723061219,-0.667836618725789,-1.29124819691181));
#375=CARTESIAN_POINT('',(-2.32845717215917,-0.675338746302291,-1.26786005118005));
#376=CARTESIAN_POINT('',(-2.3304782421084,-0.679323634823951,-1.2562252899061));
#377=CARTESIAN_POINT('',(-2.33435678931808,-0.687753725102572,-1.23310506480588));
#378=CARTESIAN_POINT('',(-2.33621437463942,-0.692198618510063,-1.22161950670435));
#379=CARTESIAN_POINT('',(-2.33976346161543,-0.701543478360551,-1.19881668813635));
#380=CARTESIAN_POINT('',(-2.3414550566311,-0.706443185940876,-1.18749933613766));
#381=CARTESIAN_POINT('',(-2.34466971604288,-0.716692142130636,-1.16505055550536));
#382=CARTESIAN_POINT('',(-2.34619283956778,-0.722041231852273,-1.15391906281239));
#383=CARTESIAN_POINT('',(-2.34906816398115,-0.733182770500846,-1.13185950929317));
#384=CARTESIAN_POINT('',(-2.35042038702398,-0.738975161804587,-1.12093142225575));
#385=CARTESIAN_POINT('',(-2.35295150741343,-0.75099647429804,-1.09929603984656));
#386=CARTESIAN_POINT('',(-2.35413038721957,-0.757225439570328,-1.08858876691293));
#387=CARTESIAN_POINT('',(-2.35631242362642,-0.770112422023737,-1.06741220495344));
#388=CARTESIAN_POINT('',(-2.35731552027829,-0.776770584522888,-1.0569429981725));
#389=CARTESIAN_POINT('',(-2.35914359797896,-0.790507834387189,-1.03625957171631));
#390=CARTESIAN_POINT('',(-2.35996847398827,-0.797587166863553,-1.02604550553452));
#391=CARTESIAN_POINT('',(-2.3614376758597,-0.812157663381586,-1.00588959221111));
#392=CARTESIAN_POINT('',(-2.36208185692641,-0.81964915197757,-0.995947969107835));
#393=CARTESIAN_POINT('',(-2.36318662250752,-0.835024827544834,-0.976365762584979));
#394=CARTESIAN_POINT('',(-2.36364724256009,-0.84290893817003,-0.966725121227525));
#395=CARTESIAN_POINT('',(-2.36438476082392,-0.859053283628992,-0.947765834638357));
#396=CARTESIAN_POINT('',(-2.36466175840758,-0.867313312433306,-0.938447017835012));
#397=CARTESIAN_POINT('',(-2.36503230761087,-0.884196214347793,-0.920145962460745));
#398=CARTESIAN_POINT('',(-2.3651259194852,-0.892818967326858,-0.911163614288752));
#399=CARTESIAN_POINT('',(-2.36513000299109,-0.910413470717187,-0.89354952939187));
#400=CARTESIAN_POINT('',(-2.36504049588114,-0.919385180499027,-0.884917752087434));
#401=CARTESIAN_POINT('',(-2.36467864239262,-0.937663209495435,-0.868018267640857));
#402=CARTESIAN_POINT('',(-2.36440627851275,-0.946969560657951,-0.859750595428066));
#403=CARTESIAN_POINT('',(-2.36367900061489,-0.965901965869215,-0.843592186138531));
#404=CARTESIAN_POINT('',(-2.36322403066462,-0.97552811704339,-0.83570156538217));
#405=CARTESIAN_POINT('',(-2.36213188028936,-0.995084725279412,-0.820309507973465));
#406=CARTESIAN_POINT('',(-2.36149460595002,-1.0050153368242,-0.812808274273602));
#407=CARTESIAN_POINT('',(-2.36003800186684,-1.02516488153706,-0.798206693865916));
#408=CARTESIAN_POINT('',(-2.3592185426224,-1.03538401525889,-0.791106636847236));
#409=CARTESIAN_POINT('',(-2.35739943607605,-1.05608322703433,-0.77732572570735));
#410=CARTESIAN_POINT('',(-2.35639981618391,-1.06656326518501,-0.770644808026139));
#411=CARTESIAN_POINT('',(-2.35422388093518,-1.08775998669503,-0.757715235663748));
#412=CARTESIAN_POINT('',(-2.35304767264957,-1.09847652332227,-0.751466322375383));
#413=CARTESIAN_POINT('',(-2.3505212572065,-1.1201289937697,-0.739407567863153));
#414=CARTESIAN_POINT('',(-2.34917110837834,-1.13106485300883,-0.733597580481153));
#415=CARTESIAN_POINT('',(-2.34629960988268,-1.15313863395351,-0.722422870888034));
#416=CARTESIAN_POINT('',(-2.34477827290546,-1.16427654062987,-0.717058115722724));
#417=CARTESIAN_POINT('',(-2.34156716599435,-1.18673700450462,-0.706779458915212));
#418=CARTESIAN_POINT('',(-2.33987736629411,-1.19805959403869,-0.701865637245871));
#419=CARTESIAN_POINT('',(-2.33633210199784,-1.2208719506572,-0.692493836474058));
#420=CARTESIAN_POINT('',(-2.33447656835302,-1.2323617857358,-0.688036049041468));
#421=CARTESIAN_POINT('',(-2.33060261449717,-1.25549111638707,-0.679580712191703));
#422=CARTESIAN_POINT('',(-2.32858408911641,-1.2671307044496,-0.675583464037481));
#423=CARTESIAN_POINT('',(-2.32438689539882,-1.29054183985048,-0.668053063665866));
#424=CARTESIAN_POINT('',(-2.32220809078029,-1.30231349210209,-0.664520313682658));
#425=CARTESIAN_POINT('',(-2.31769491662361,-1.32596264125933,-0.657924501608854));
#426=CARTESIAN_POINT('',(-2.31536049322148,-1.33784017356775,-0.654861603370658));
#427=CARTESIAN_POINT('',(-2.31054161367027,-1.36167732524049,-0.649208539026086));
#428=CARTESIAN_POINT('',(-2.30805715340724,-1.37363694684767,-0.646618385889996));
#429=CARTESIAN_POINT('',(-2.30294285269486,-1.39761906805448,-0.641911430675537));
#430=CARTESIAN_POINT('',(-2.30031300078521,-1.40964157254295,-0.639794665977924));
#431=CARTESIAN_POINT('',(-2.294912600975,-1.43373037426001,-0.636034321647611));
#432=CARTESIAN_POINT('',(-2.29214203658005,-1.44579667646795,-0.634390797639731));
#433=CARTESIAN_POINT('',(-2.28646488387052,-1.46995414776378,-0.631575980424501));
#434=CARTESIAN_POINT('',(-2.28355827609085,-1.48204532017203,-0.630404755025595));
#435=CARTESIAN_POINT('',(-2.27761371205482,-1.50623376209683,-0.628532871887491));
#436=CARTESIAN_POINT('',(-2.27457573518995,-1.51833103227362,-0.627832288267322));
#437=CARTESIAN_POINT('',(-2.2683730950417,-1.54251322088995,-0.626899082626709));
#438=CARTESIAN_POINT('',(-2.26520841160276,-1.55459813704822,-0.626666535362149));
#439=CARTESIAN_POINT('',(-2.26198297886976,-1.56666666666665,-0.626666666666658));
#440=B_SPLINE_CURVE_WITH_KNOTS('',3,(#358,#359,#360,#361,#362,#363,#364,#365,#366,#367,#368,
#369,#370,#371,#372,#373,#374,#375,#376,#377,#378,#379,#380,#381,#382,#383,#384,#385,#386,#387,
#388,#389,#390,#391,#392,#393,#394,#395,#396,#397,#398,#399,#400,#401,#402,#403,#404,#405,#406,
#407,#408,#409,#410,#411,#412,#413,#414,#415,#416,#417,#418,#419,#420,#421,#422,#423,#424,#425,
#426,#427,#428,#429,#430,#431,#432,#433,#434,#435,#436,#437,#438,#439),.UNSPECIFIED.,.F.,.F.,(4,
2,2,2,2,2,2,2,2,2,2,2,2,2,2,2,2,2,2,2,2,2,2,2,2,2,2,2,2,2,2,2,2,2,2,2,2,2,2,2,4),(0.,
0.0373787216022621,0.0747444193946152,0.112100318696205,0.149450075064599,0.186797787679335,
0.224148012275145,0.261505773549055,0.298876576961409,0.336255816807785,0.373610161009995,
0.410943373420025,0.448263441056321,0.485578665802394,0.522897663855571,0.5602293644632,
0.597583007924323,0.634966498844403,0.672342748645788,0.70969875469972,0.747042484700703,
0.784381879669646,0.821724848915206,0.859079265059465,0.896452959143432,0.933853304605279,
0.971247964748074,1.00862004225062,1.04597961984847,1.08333642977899,1.12069985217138,
1.15807891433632,1.19548229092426,1.23291784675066,1.27036642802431,1.30781603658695,
1.34526860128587,1.38272556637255,1.42018790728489,1.45765614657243,1.4951303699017),.UNSPECIFIED.);
#441=CARTESIAN_POINT('',(-2.26198297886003,-0.62666666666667,-1.5666666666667));
#442=VERTEX_POINT('',#441);
#443=EDGE_CURVE('E107',#442,#355,#440,.T.);
#444=ORIENTED_EDGE('',*,*,#443,.F.);
#445=CARTESIAN_POINT('',(-2.26198297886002,-0.626666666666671,-1.5666666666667));
#446=CARTESIAN_POINT('',(-2.25890939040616,-0.626667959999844,-1.5781665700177));
#447=CARTESIAN_POINT('',(-2.25580100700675,-0.626678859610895,-1.58965715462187));
#448=CARTESIAN_POINT('',(-2.24940641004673,-0.6267090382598,-1.61301958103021));
#449=CARTESIAN_POINT('',(-2.24611777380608,-0.626728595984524,-1.62489075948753));
#450=CARTESIAN_POINT('',(-2.2393789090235,-0.626764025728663,-1.64893324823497));
#451=CARTESIAN_POINT('',(-2.23592671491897,-0.626779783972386,-1.66110400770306));
#452=CARTESIAN_POINT('',(-2.22887838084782,-0.62680162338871,-1.68566395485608));
#453=CARTESIAN_POINT('',(-2.22528074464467,-0.626807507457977,-1.69805271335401));
#454=CARTESIAN_POINT('',(-2.21796095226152,-0.62680720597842,-1.72296657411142));
#455=CARTESIAN_POINT('',(-2.21423778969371,-0.626800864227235,-1.73549138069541));
#456=CARTESIAN_POINT('',(-2.20668807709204,-0.626778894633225,-1.76059497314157));
#457=CARTESIAN_POINT('',(-2.20286102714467,-0.626763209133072,-1.77317360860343));
#458=CARTESIAN_POINT('',(-2.19512675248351,-0.626727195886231,-1.7983024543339));
#459=CARTESIAN_POINT('',(-2.19121954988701,-0.6267068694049,-1.81085267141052));
#460=CARTESIAN_POINT('',(-2.18334912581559,-0.626679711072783,-1.8358420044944));
#461=CARTESIAN_POINT('',(-2.17938646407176,-0.626672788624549,-1.84828129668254));
#462=CARTESIAN_POINT('',(-2.17144141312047,-0.62666063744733,-1.87294574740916));
#463=CARTESIAN_POINT('',(-2.16746023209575,-0.626655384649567,-1.88517129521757));
#464=CARTESIAN_POINT('',(-2.15948191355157,-0.626632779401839,-1.90941347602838));
#465=CARTESIAN_POINT('',(-2.15548591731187,-0.626615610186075,-1.92143048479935));
#466=CARTESIAN_POINT('',(-2.14745318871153,-0.62658573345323,-1.94533538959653));
#467=CARTESIAN_POINT('',(-2.1434171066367,-0.626572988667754,-1.95722350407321));
#468=CARTESIAN_POINT('',(-2.13527849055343,-0.626555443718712,-1.98095075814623));
#469=CARTESIAN_POINT('',(-2.13117610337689,-0.626550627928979,-1.99278994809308));
#470=CARTESIAN_POINT('',(-2.1228771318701,-0.626551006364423,-2.01649936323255));
#471=CARTESIAN_POINT('',(-2.11868018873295,-0.626556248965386,-2.02836946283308));
#472=CARTESIAN_POINT('',(-2.11016262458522,-0.626574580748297,-2.05222057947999));
#473=CARTESIAN_POINT('',(-2.10584113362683,-0.626587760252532,-2.06420128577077));
#474=CARTESIAN_POINT('',(-2.09704313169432,-0.626616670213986,-2.08835324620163));
#475=CARTESIAN_POINT('',(-2.0925652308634,-0.626632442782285,-2.10052399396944));
#476=CARTESIAN_POINT('',(-2.08342122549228,-0.62665736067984,-2.12513535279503));
#477=CARTESIAN_POINT('',(-2.07875319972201,-0.626666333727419,-2.13757525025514));
#478=CARTESIAN_POINT('',(-2.07404519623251,-0.626666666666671,-2.15));
#479=B_SPLINE_CURVE_WITH_KNOTS('',3,(#445,#446,#447,#448,#449,#450,#451,#452,#453,#454,#455,
#456,#457,#458,#459,#460,#461,#462,#463,#464,#465,#466,#467,#468,#469,#470,#471,#472,#473,#474,
#475,#476,#477,#478),.UNSPECIFIED.,.F.,.F.,(4,2,2,2,2,2,2,2,2,2,2,2,2,2,2,2,4),(0.,
0.0357105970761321,0.0726652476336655,0.110617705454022,0.149319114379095,0.188518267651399,
0.227961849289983,0.267394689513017,0.306560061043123,0.345132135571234,0.383123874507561,
0.420787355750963,0.458376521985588,0.496146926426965,0.534355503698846,0.573260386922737,
0.613120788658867),.UNSPECIFIED.);
#480=CARTESIAN_POINT('',(-2.07404519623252,-0.62666666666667,-2.15));
#481=VERTEX_POINT('',#480);
#482=EDGE_CURVE('E121',#442,#481,#479,.T.);
#483=ORIENTED_EDGE('',*,*,#482,.T.);
#484=CARTESIAN_POINT('',(-2.07404519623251,-0.626666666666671,-2.15));
#485=CARTESIAN_POINT('',(-2.07704980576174,-0.599465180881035,-2.14999909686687));
#486=CARTESIAN_POINT('',(-2.07986503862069,-0.572242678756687,-2.14998150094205));
#487=CARTESIAN_POINT('',(-2.08506116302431,-0.518256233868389,-2.14993301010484));
#488=CARTESIAN_POINT('',(-2.08744902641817,-0.491492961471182,-2.14990236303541));
#489=CARTESIAN_POINT('',(-2.09181031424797,-0.438353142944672,-2.14984684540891));
#490=CARTESIAN_POINT('',(-2.09378962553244,-0.411977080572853,-2.14982189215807));
#491=CARTESIAN_POINT('',(-2.09735237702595,-0.359540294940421,-2.14978796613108));
#492=CARTESIAN_POINT('',(-2.09894059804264,-0.333479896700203,-2.14977879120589));
#493=CARTESIAN_POINT('',(-2.10173784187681,-0.281603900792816,-2.14977968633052));
#494=CARTESIAN_POINT('',(-2.10295054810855,-0.255788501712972,-2.1497895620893));
#495=CARTESIAN_POINT('',(-2.10501180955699,-0.204333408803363,-2.14982468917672));
#496=CARTESIAN_POINT('',(-2.10586297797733,-0.178693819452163,-2.14984982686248));
#497=CARTESIAN_POINT('',(-2.10721463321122,-0.12752320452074,-2.14990488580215));
#498=CARTESIAN_POINT('',(-2.10771671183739,-0.101992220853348,-2.14993478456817));
#499=CARTESIAN_POINT('',(-2.10838218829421,-0.0509741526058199,-2.14998233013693));
#500=CARTESIAN_POINT('',(-2.10854622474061,-0.0254870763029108,-2.15));
#501=CARTESIAN_POINT('',(-2.10854622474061,0.0254870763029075,-2.15));
#502=CARTESIAN_POINT('',(-2.10838218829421,0.0509741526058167,-2.14998233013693));
#503=CARTESIAN_POINT('',(-2.10771671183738,0.101992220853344,-2.14993478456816));
#504=CARTESIAN_POINT('',(-2.10721463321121,0.127523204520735,-2.14990488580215));
#505=CARTESIAN_POINT('',(-2.10586297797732,0.178693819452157,-2.14984982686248));
#506=CARTESIAN_POINT('',(-2.10501180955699,0.204333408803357,-2.14982468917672));
#507=CARTESIAN_POINT('',(-2.10295054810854,0.255788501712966,-2.1497895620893));
#508=CARTESIAN_POINT('',(-2.1017378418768,0.28160390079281,-2.14977968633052));
#509=CARTESIAN_POINT('',(-2.09894059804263,0.333479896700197,-2.14977879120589));
#510=CARTESIAN_POINT('',(-2.09735237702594,0.359540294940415,-2.14978796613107));
#511=CARTESIAN_POINT('',(-2.09378962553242,0.411977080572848,-2.14982189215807));
#512=CARTESIAN_POINT('',(-2.09181031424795,0.438353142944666,-2.14984684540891));
#513=CARTESIAN_POINT('',(-2.08744902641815,0.491492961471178,-2.14990236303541));
#514=CARTESIAN_POINT('',(-2.08506116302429,0.518256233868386,-2.14993301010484));
#515=CARTESIAN_POINT('',(-2.07986503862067,0.572242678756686,-2.14998150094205));
#516=CARTESIAN_POINT('',(-2.07704980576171,0.599465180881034,-2.14999909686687));
#517=CARTESIAN_POINT('',(-2.07404519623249,0.62666666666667,-2.15));
#518=B_SPLINE_CURVE_WITH_KNOTS('',3,(#484,#485,#486,#487,#488,#489,#490,#491,#492,#493,#494,
#495,#496,#497,#498,#499,#500,#501,#502,#503,#504,#505,#506,#507,#508,#509,#510,#511,#512,#513,
#514,#515,#516,#517),.UNSPECIFIED.,.F.,.F.,(4,2,2,2,2,2,2,2,2,2,2,2,2,2,2,2,4),(0.,
0.0821002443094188,0.162706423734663,0.242054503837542,0.320378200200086,0.397907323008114,
0.474866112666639,0.551471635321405,0.627932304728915,0.704392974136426,0.780998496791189,
0.857957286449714,0.935486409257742,1.01381010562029,1.09315818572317,1.17376436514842,
1.25586460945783),.UNSPECIFIED.);
#519=CARTESIAN_POINT('',(-2.07404519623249,0.62666666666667,-2.15));
#520=VERTEX_POINT('',#519);
#521=EDGE_CURVE('E135',#481,#520,#518,.T.);
#522=ORIENTED_EDGE('',*,*,#521,.T.);
#523=CARTESIAN_POINT('',(-2.07404519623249,0.62666666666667,-2.15));
#524=CARTESIAN_POINT('',(-2.07875319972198,0.626666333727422,-2.13757525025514));
#525=CARTESIAN_POINT('',(-2.08342122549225,0.626657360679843,-2.12513535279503));
#526=CARTESIAN_POINT('',(-2.09256523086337,0.626632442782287,-2.10052399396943));
#527=CARTESIAN_POINT('',(-2.0970431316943,0.626616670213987,-2.08835324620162));
#528=CARTESIAN_POINT('',(-2.1058411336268,0.626587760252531,-2.06420128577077));
#529=CARTESIAN_POINT('',(-2.1101626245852,0.626574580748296,-2.05222057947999));
#530=CARTESIAN_POINT('',(-2.11868018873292,0.626556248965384,-2.02836946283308));
#531=CARTESIAN_POINT('',(-2.12287713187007,0.626551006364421,-2.01649936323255));
#532=CARTESIAN_POINT('',(-2.13117610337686,0.626550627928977,-1.99278994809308));
#533=CARTESIAN_POINT('',(-2.13527849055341,0.62655544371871,-1.98095075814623));
#534=CARTESIAN_POINT('',(-2.14341710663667,0.626572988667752,-1.95722350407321));
#535=CARTESIAN_POINT('',(-2.1474531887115,0.626585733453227,-1.94533538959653));
#536=CARTESIAN_POINT('',(-2.15548591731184,0.626615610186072,-1.92143048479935));
#537=CARTESIAN_POINT('',(-2.15948191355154,0.626632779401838,-1.90941347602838));
#538=CARTESIAN_POINT('',(-2.16746023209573,0.626655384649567,-1.88517129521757));
#539=CARTESIAN_POINT('',(-2.17144141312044,0.626660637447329,-1.87294574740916));
#540=CARTESIAN_POINT('',(-2.17938646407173,0.626672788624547,-1.84828129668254));
#541=CARTESIAN_POINT('',(-2.18334912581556,0.62667971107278,-1.8358420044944));
#542=CARTESIAN_POINT('',(-2.19121954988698,0.626706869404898,-1.81085267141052));
#543=CARTESIAN_POINT('',(-2.19512675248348,0.62672719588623,-1.7983024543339));
#544=CARTESIAN_POINT('',(-2.20286102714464,0.626763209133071,-1.77317360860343));
#545=CARTESIAN_POINT('',(-2.20668807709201,0.626778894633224,-1.76059497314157));
#546=CARTESIAN_POINT('',(-2.21423778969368,0.626800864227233,-1.73549138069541));
#547=CARTESIAN_POINT('',(-2.2179609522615,0.626807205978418,-1.72296657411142));
#548=CARTESIAN_POINT('',(-2.22528074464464,0.626807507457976,-1.698052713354));
#549=CARTESIAN_POINT('',(-2.22887838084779,0.626801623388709,-1.68566395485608));
#550=CARTESIAN_POINT('',(-2.23592671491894,0.626779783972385,-1.66110400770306));
#551=CARTESIAN_POINT('',(-2.23937890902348,0.626764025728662,-1.64893324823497));
#552=CARTESIAN_POINT('',(-2.24611777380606,0.626728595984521,-1.62489075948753));
#553=CARTESIAN_POINT('',(-2.2494064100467,0.626709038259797,-1.61301958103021));
#554=CARTESIAN_POINT('',(-2.25580100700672,0.626678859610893,-1.58965715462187));
#555=CARTESIAN_POINT('',(-2.25890939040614,0.626667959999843,-1.5781665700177));
#556=CARTESIAN_POINT('',(-2.26198297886,0.62666666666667,-1.5666666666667));
#557=B_SPLINE_CURVE_WITH_KNOTS('',3,(#523,#524,#525,#526,#527,#528,#529,#530,#531,#532,#533,
#534,#535,#536,#537,#538,#539,#540,#541,#542,#543,#544,#545,#546,#547,#548,#549,#550,#551,#552,
#553,#554,#555,#556),.UNSPECIFIED.,.F.,.F.,(4,2,2,2,2,2,2,2,2,2,2,2,2,2,2,2,4),(0.,
0.0398604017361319,0.0787652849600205,0.116973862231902,0.154744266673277,0.192333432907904,
0.229996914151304,0.26798865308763,0.306560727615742,0.345726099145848,0.385158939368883,
0.424602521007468,0.463801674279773,0.502503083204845,0.540455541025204,0.577410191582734,
0.613120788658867),.UNSPECIFIED.);
#558=CARTESIAN_POINT('',(-2.26198297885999,0.62666666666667,-1.5666666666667));
#559=VERTEX_POINT('',#558);
#560=EDGE_CURVE('E149',#520,#559,#557,.T.);
#561=ORIENTED_EDGE('',*,*,#560,.T.);
#562=CARTESIAN_POINT('',(-2.26198297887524,1.56666666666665,-0.626666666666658));
#563=CARTESIAN_POINT('',(-2.2652001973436,1.55462889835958,-0.626666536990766));
#564=CARTESIAN_POINT('',(-2.26835697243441,1.54257482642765,-0.626897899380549));
#565=CARTESIAN_POINT('',(-2.2745438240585,1.51845661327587,-0.627826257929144));
#566=CARTESIAN_POINT('',(-2.27757394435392,1.50639247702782,-0.628523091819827));
#567=CARTESIAN_POINT('',(-2.28350314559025,1.48227142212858,-0.630384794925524));
#568=CARTESIAN_POINT('',(-2.28640226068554,1.47021450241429,-0.631549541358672));
#569=CARTESIAN_POINT('',(-2.29206511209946,1.44612548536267,-0.634348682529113));
#570=CARTESIAN_POINT('',(-2.29482887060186,1.43409338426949,-0.635983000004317));
#571=CARTESIAN_POINT('',(-2.30021667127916,1.41007177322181,-0.639722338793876));
#572=CARTESIAN_POINT('',(-2.30284072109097,1.39808226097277,-0.641827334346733));
#573=CARTESIAN_POINT('',(-2.30794477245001,1.37416378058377,-0.646508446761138));
#574=CARTESIAN_POINT('',(-2.31042476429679,1.36223481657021,-0.649084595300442));
#575=CARTESIAN_POINT('',(-2.31523635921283,1.3384555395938,-0.654707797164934));
#576=CARTESIAN_POINT('',(-2.31756793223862,1.32660524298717,-0.657754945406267));
#577=CARTESIAN_POINT('',(-2.32207839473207,1.30300155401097,-0.664319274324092));
#578=CARTESIAN_POINT('',(-2.3242572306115,1.29124819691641,-0.667836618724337));
#579=CARTESIAN_POINT('',(-2.328457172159,1.26786005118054,-0.675338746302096));
#580=CARTESIAN_POINT('',(-2.33047824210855,1.25622528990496,-0.679323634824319));
#581=CARTESIAN_POINT('',(-2.3343567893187,1.23310506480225,-0.68775372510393));
#582=CARTESIAN_POINT('',(-2.33621437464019,1.22161950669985,-0.692198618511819));
#583=CARTESIAN_POINT('',(-2.3397634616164,1.19881668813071,-0.701543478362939));
#584=CARTESIAN_POINT('',(-2.34145505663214,1.18749933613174,-0.706443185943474));
#585=CARTESIAN_POINT('',(-2.34466971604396,1.16505055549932,-0.716692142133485));
#586=CARTESIAN_POINT('',(-2.34619283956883,1.1539190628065,-0.722041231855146));
#587=CARTESIAN_POINT('',(-2.34906816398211,1.13185950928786,-0.733182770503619));
#588=CARTESIAN_POINT('',(-2.35042038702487,1.12093142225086,-0.738975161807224));
#589=CARTESIAN_POINT('',(-2.35295150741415,1.09929603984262,-0.750996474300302));
#590=CARTESIAN_POINT('',(-2.35413038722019,1.08858876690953,-0.757225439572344));
#591=CARTESIAN_POINT('',(-2.35631242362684,1.06741220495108,-0.770112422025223));
#592=CARTESIAN_POINT('',(-2.35731552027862,1.05694299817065,-0.77677058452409));
#593=CARTESIAN_POINT('',(-2.3591435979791,1.03625957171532,-0.790507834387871));
#594=CARTESIAN_POINT('',(-2.35996847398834,1.02604550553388,-0.797587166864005));
#595=CARTESIAN_POINT('',(-2.36143767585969,1.00588959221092,-0.812157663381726));
#596=CARTESIAN_POINT('',(-2.36208185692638,0.995947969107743,-0.81964915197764));
#597=CARTESIAN_POINT('',(-2.36318662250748,0.976365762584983,-0.835024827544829));
#598=CARTESIAN_POINT('',(-2.36364724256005,0.966725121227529,-0.842908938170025));
#599=CARTESIAN_POINT('',(-2.36438476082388,0.947765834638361,-0.859053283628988));
#600=CARTESIAN_POINT('',(-2.36466175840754,0.938447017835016,-0.867313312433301));
#601=CARTESIAN_POINT('',(-2.36503230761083,0.920145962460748,-0.884196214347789));
#602=CARTESIAN_POINT('',(-2.36512591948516,0.911163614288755,-0.892818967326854));
#603=CARTESIAN_POINT('',(-2.36513000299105,0.893549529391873,-0.910413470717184));
#604=CARTESIAN_POINT('',(-2.3650404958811,0.884917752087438,-0.919385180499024));
#605=CARTESIAN_POINT('',(-2.36467864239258,0.868018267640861,-0.937663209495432));
#606=CARTESIAN_POINT('',(-2.36440627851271,0.85975059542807,-0.946969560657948));
#607=CARTESIAN_POINT('',(-2.36367900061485,0.843592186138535,-0.965901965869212));
#608=CARTESIAN_POINT('',(-2.36322403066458,0.835701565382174,-0.975528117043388));
#609=CARTESIAN_POINT('',(-2.36213188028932,0.820309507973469,-0.99508472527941));
#610=CARTESIAN_POINT('',(-2.36149460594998,0.812808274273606,-1.0050153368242));
#611=CARTESIAN_POINT('',(-2.3600380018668,0.798206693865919,-1.02516488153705));
#612=CARTESIAN_POINT('',(-2.35921854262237,0.791106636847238,-1.03538401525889));
#613=CARTESIAN_POINT('',(-2.35739943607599,0.777325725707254,-1.05608322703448));
#614=CARTESIAN_POINT('',(-2.35639981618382,0.770644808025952,-1.06656326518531));
#615=CARTESIAN_POINT('',(-2.35422388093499,0.75771523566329,-1.0877599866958));
#616=CARTESIAN_POINT('',(-2.3530476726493,0.751466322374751,-1.09847652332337));
#617=CARTESIAN_POINT('',(-2.35052125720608,0.739407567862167,-1.12012899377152));
#618=CARTESIAN_POINT('',(-2.34917110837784,0.733597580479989,-1.13106485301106));
#619=CARTESIAN_POINT('',(-2.34629960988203,0.72242287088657,-1.1531386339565));
#620=CARTESIAN_POINT('',(-2.34477827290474,0.717058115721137,-1.16427654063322));
#621=CARTESIAN_POINT('',(-2.34156716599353,0.706779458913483,-1.18673700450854));
#622=CARTESIAN_POINT('',(-2.33987736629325,0.701865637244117,-1.19805959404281));
#623=CARTESIAN_POINT('',(-2.33633210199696,0.692493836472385,-1.22087195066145));
#624=CARTESIAN_POINT('',(-2.33447656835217,0.688036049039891,-1.23236178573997));
#625=CARTESIAN_POINT('',(-2.33060261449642,0.679580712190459,-1.25549111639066));
#626=CARTESIAN_POINT('',(-2.32858408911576,0.675583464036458,-1.26713070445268));
#627=CARTESIAN_POINT('',(-2.3243868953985,0.668053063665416,-1.29054183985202));
#628=CARTESIAN_POINT('',(-2.3222080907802,0.664520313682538,-1.30231349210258));
#629=CARTESIAN_POINT('',(-2.31769491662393,0.657924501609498,-1.32596264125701));
#630=CARTESIAN_POINT('',(-2.31536049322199,0.654861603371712,-1.33784017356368));
#631=CARTESIAN_POINT('',(-2.31054161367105,0.649208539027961,-1.36167732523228));
#632=CARTESIAN_POINT('',(-2.30805715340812,0.64661838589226,-1.37363694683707));
#633=CARTESIAN_POINT('',(-2.30294285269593,0.641911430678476,-1.39761906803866));
#634=CARTESIAN_POINT('',(-2.30031300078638,0.639794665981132,-1.40964157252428));
#635=CARTESIAN_POINT('',(-2.29491260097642,0.636034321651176,-1.43373037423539));
#636=CARTESIAN_POINT('',(-2.29214203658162,0.634390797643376,-1.44579667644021));
#637=CARTESIAN_POINT('',(-2.28646488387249,0.631575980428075,-1.46995414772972));
#638=CARTESIAN_POINT('',(-2.28355827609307,0.630404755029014,-1.48204532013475));
#639=CARTESIAN_POINT('',(-2.27761371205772,0.628532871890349,-1.50623376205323));
#640=CARTESIAN_POINT('',(-2.27457573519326,0.627832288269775,-1.51833103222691));
#641=CARTESIAN_POINT('',(-2.26837309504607,0.626899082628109,-1.54251322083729));
#642=CARTESIAN_POINT('',(-2.26520841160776,0.626666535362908,-1.55459813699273));
#643=CARTESIAN_POINT('',(-2.26198297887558,0.626666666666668,-1.5666666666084));
#644=B_SPLINE_CURVE_WITH_KNOTS('',3,(#562,#563,#564,#565,#566,#567,#568,#569,#570,#571,#572,
#573,#574,#575,#576,#577,#578,#579,#580,#581,#582,#583,#584,#585,#586,#587,#588,#589,#590,#591,
#592,#593,#594,#595,#596,#597,#598,#599,#600,#601,#602,#603,#604,#605,#606,#607,#608,#609,#610,
#611,#612,#613,#614,#615,#616,#617,#618,#619,#620,#621,#622,#623,#624,#625,#626,#627,#628,#629,
#630,#631,#632,#633,#634,#635,#636,#637,#638,#639,#640,#641,#642,#643),.UNSPECIFIED.,.F.,.F.,(4,
2,2,2,2,2,2,2,2,2,2,2,2,2,2,2,2,2,2,2,2,2,2,2,2,2,2,2,2,2,2,2,2,2,2,2,2,2,2,2,4),(0.,
0.0373787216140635,0.074744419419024,0.112100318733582,0.149450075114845,0.186797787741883,
0.224148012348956,0.261505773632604,0.298876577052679,0.336255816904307,0.373610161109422,
0.410943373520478,0.448263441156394,0.485578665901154,0.522897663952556,0.560229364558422,
0.597583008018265,0.63496649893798,0.672342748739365,0.709698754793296,0.747042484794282,
0.784381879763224,0.821724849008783,0.859079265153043,0.89645295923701,0.933853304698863,
0.971247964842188,1.00862004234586,1.04597961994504,1.08333642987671,1.1206998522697,
1.1580789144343,1.19548229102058,1.2329178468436,1.27036642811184,1.30781603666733,
1.34526860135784,1.38272556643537,1.42018790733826,1.45765614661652,1.49513036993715),.UNSPECIFIED.);
#645=CARTESIAN_POINT('',(-2.26198297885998,1.5666666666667,-0.62666666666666));
#646=VERTEX_POINT('',#645);
#647=EDGE_CURVE('E163',#646,#559,#644,.T.);
#648=ORIENTED_EDGE('',*,*,#647,.F.);
#649=CARTESIAN_POINT('',(-2.26198297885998,1.5666666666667,-0.626666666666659));
#650=CARTESIAN_POINT('',(-2.25890939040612,1.5781665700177,-0.626667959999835));
#651=CARTESIAN_POINT('',(-2.2558010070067,1.58965715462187,-0.626678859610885));
#652=CARTESIAN_POINT('',(-2.24940641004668,1.61301958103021,-0.626709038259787));
#653=CARTESIAN_POINT('',(-2.24611777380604,1.62489075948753,-0.62672859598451));
#654=CARTESIAN_POINT('',(-2.23937890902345,1.64893324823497,-0.626764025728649));
#655=CARTESIAN_POINT('',(-2.23592671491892,1.66110400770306,-0.626779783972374));
#656=CARTESIAN_POINT('',(-2.22887838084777,1.68566395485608,-0.6268016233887));
#657=CARTESIAN_POINT('',(-2.22528074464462,1.698052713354,-0.626807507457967));
#658=CARTESIAN_POINT('',(-2.21796095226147,1.72296657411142,-0.626807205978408));
#659=CARTESIAN_POINT('',(-2.21423778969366,1.73549138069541,-0.626800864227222));
#660=CARTESIAN_POINT('',(-2.20668807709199,1.76059497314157,-0.626778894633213));
#661=CARTESIAN_POINT('',(-2.20286102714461,1.77317360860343,-0.626763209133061));
#662=CARTESIAN_POINT('',(-2.19512675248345,1.7983024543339,-0.626727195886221));
#663=CARTESIAN_POINT('',(-2.19121954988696,1.81085267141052,-0.626706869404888));
#664=CARTESIAN_POINT('',(-2.18334912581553,1.8358420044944,-0.62667971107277));
#665=CARTESIAN_POINT('',(-2.17938646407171,1.84828129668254,-0.626672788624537));
#666=CARTESIAN_POINT('',(-2.17144141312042,1.87294574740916,-0.626660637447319));
#667=CARTESIAN_POINT('',(-2.1674602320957,1.88517129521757,-0.626655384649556));
#668=CARTESIAN_POINT('',(-2.15948191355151,1.90941347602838,-0.626632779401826));
#669=CARTESIAN_POINT('',(-2.15548591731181,1.92143048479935,-0.62661561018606));
#670=CARTESIAN_POINT('',(-2.14745318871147,1.94533538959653,-0.626585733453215));
#671=CARTESIAN_POINT('',(-2.14341710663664,1.95722350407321,-0.62657298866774));
#672=CARTESIAN_POINT('',(-2.13527849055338,1.98095075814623,-0.6265554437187));
#673=CARTESIAN_POINT('',(-2.13117610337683,1.99278994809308,-0.626550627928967));
#674=CARTESIAN_POINT('',(-2.12287713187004,2.01649936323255,-0.62655100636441));
#675=CARTESIAN_POINT('',(-2.11868018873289,2.02836946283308,-0.626556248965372));
#676=CARTESIAN_POINT('',(-2.11016262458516,2.05222057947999,-0.626574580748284));
#677=CARTESIAN_POINT('',(-2.10584113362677,2.06420128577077,-0.62658776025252));
#678=CARTESIAN_POINT('',(-2.09704313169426,2.08835324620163,-0.626616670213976));
#679=CARTESIAN_POINT('',(-2.09256523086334,2.10052399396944,-0.626632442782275));
#680=CARTESIAN_POINT('',(-2.08342122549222,2.12513535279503,-0.62665736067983));
#681=CARTESIAN_POINT('',(-2.07875319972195,2.13757525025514,-0.62666633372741));
#682=CARTESIAN_POINT('',(-2.07404519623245,2.15,-0.62666666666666));
#683=B_SPLINE_CURVE_WITH_KNOTS('',3,(#649,#650,#651,#652,#653,#654,#655,#656,#657,#658,#659,
#660,#661,#662,#663,#664,#665,#666,#667,#668,#669,#670,#671,#672,#673,#674,#675,#676,#677,#678,
#679,#680,#681,#682),.UNSPECIFIED.,.F.,.F.,(4,2,2,2,2,2,2,2,2,2,2,2,2,2,2,2,4),(0.,
0.0357105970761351,0.0726652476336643,0.110617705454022,0.149319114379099,0.188518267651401,
0.227961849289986,0.267394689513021,0.306560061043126,0.345132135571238,0.383123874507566,
0.420787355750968,0.458376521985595,0.496146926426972,0.534355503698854,0.573260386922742,
0.613120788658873),.UNSPECIFIED.);
#684=CARTESIAN_POINT('',(-2.07404519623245,2.15,-0.62666666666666));
#685=VERTEX_POINT('',#684);
#686=EDGE_CURVE('E177',#646,#685,#683,.T.);
#687=ORIENTED_EDGE('',*,*,#686,.T.);
#688=CARTESIAN_POINT('',(-2.07404519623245,2.15,-0.626666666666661));
#689=CARTESIAN_POINT('',(-2.07704980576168,2.14999909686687,-0.599465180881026));
#690=CARTESIAN_POINT('',(-2.07986503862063,2.14998150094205,-0.572242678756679));
#691=CARTESIAN_POINT('',(-2.08506116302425,2.14993301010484,-0.518256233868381));
#692=CARTESIAN_POINT('',(-2.08744902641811,2.14990236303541,-0.491492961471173));
#693=CARTESIAN_POINT('',(-2.09181031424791,2.14984684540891,-0.438353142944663));
#694=CARTESIAN_POINT('',(-2.09378962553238,2.14982189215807,-0.411977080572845));
#695=CARTESIAN_POINT('',(-2.0973523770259,2.14978796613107,-0.359540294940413));
#696=CARTESIAN_POINT('',(-2.09894059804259,2.14977879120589,-0.333479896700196));
#697=CARTESIAN_POINT('',(-2.10173784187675,2.14977968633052,-0.281603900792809));
#698=CARTESIAN_POINT('',(-2.10295054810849,2.1497895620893,-0.255788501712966));
#699=CARTESIAN_POINT('',(-2.10501180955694,2.14982468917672,-0.204333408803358));
#700=CARTESIAN_POINT('',(-2.10586297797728,2.14984982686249,-0.178693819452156));
#701=CARTESIAN_POINT('',(-2.10721463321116,2.14990488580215,-0.127523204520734));
#702=CARTESIAN_POINT('',(-2.10771671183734,2.14993478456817,-0.101992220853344));
#703=CARTESIAN_POINT('',(-2.10838218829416,2.14998233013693,-0.0509741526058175));
#704=CARTESIAN_POINT('',(-2.10854622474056,2.15,-0.0254870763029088));
#705=CARTESIAN_POINT('',(-2.10854622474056,2.15,0.0254870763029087));
#706=CARTESIAN_POINT('',(-2.10838218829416,2.14998233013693,0.0509741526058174));
#707=CARTESIAN_POINT('',(-2.10771671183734,2.14993478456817,0.101992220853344));
#708=CARTESIAN_POINT('',(-2.10721463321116,2.14990488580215,0.127523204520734));
#709=CARTESIAN_POINT('',(-2.10586297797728,2.14984982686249,0.178693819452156));
#710=CARTESIAN_POINT('',(-2.10501180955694,2.14982468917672,0.204333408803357));
#711=CARTESIAN_POINT('',(-2.10295054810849,2.1497895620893,0.255788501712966));
#712=CARTESIAN_POINT('',(-2.10173784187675,2.14977968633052,0.281603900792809));
#713=CARTESIAN_POINT('',(-2.09894059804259,2.14977879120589,0.333479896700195));
#714=CARTESIAN_POINT('',(-2.0973523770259,2.14978796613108,0.359540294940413));
#715=CARTESIAN_POINT('',(-2.09378962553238,2.14982189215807,0.411977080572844));
#716=CARTESIAN_POINT('',(-2.09181031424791,2.14984684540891,0.438353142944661));
#717=CARTESIAN_POINT('',(-2.08744902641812,2.14990236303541,0.491492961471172));
#718=CARTESIAN_POINT('',(-2.08506116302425,2.14993301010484,0.51825623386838));
#719=CARTESIAN_POINT('',(-2.07986503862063,2.14998150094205,0.572242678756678));
#720=CARTESIAN_POINT('',(-2.07704980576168,2.14999909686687,0.599465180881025));
#721=CARTESIAN_POINT('',(-2.07404519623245,2.15,0.62666666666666));
#722=B_SPLINE_CURVE_WITH_KNOTS('',3,(#688,#689,#690,#691,#692,#693,#694,#695,#696,#697,#698,
#699,#700,#701,#702,#703,#704,#705,#706,#707,#708,#709,#710,#711,#712,#713,#714,#715,#716,#717,
#718,#719,#720,#721),.UNSPECIFIED.,.F.,.F.,(4,2,2,2,2,2,2,2,2,2,2,2,2,2,2,2,4),(0.,
0.0821002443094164,0.162706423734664,0.24205450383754,0.320378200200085,0.39790732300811,
0.474866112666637,0.551471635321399,0.627932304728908,0.704392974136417,0.780998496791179,
0.857957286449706,0.935486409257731,1.01381010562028,1.09315818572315,1.1737643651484,
1.25586460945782),.UNSPECIFIED.);
#723=CARTESIAN_POINT('',(-2.07404519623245,2.15,0.62666666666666));
#724=VERTEX_POINT('',#723);
#725=EDGE_CURVE('E191',#685,#724,#722,.T.);
#726=ORIENTED_EDGE('',*,*,#725,.T.);
#727=CARTESIAN_POINT('',(-2.07404519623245,2.15,0.62666666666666));
#728=CARTESIAN_POINT('',(-2.07875319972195,2.13757525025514,0.62666633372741));
#729=CARTESIAN_POINT('',(-2.08342122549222,2.12513535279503,0.62665736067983));
#730=CARTESIAN_POINT('',(-2.09256523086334,2.10052399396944,0.626632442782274));
#731=CARTESIAN_POINT('',(-2.09704313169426,2.08835324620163,0.626616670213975));
#732=CARTESIAN_POINT('',(-2.10584113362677,2.06420128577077,0.62658776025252));
#733=CARTESIAN_POINT('',(-2.11016262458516,2.05222057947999,0.626574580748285));
#734=CARTESIAN_POINT('',(-2.11868018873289,2.02836946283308,0.626556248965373));
#735=CARTESIAN_POINT('',(-2.12287713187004,2.01649936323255,0.626551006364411));
#736=CARTESIAN_POINT('',(-2.13117610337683,1.99278994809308,0.626550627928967));
#737=CARTESIAN_POINT('',(-2.13527849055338,1.98095075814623,0.6265554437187));
#738=CARTESIAN_POINT('',(-2.14341710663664,1.95722350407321,0.626572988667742));
#739=CARTESIAN_POINT('',(-2.14745318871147,1.94533538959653,0.626585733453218));
#740=CARTESIAN_POINT('',(-2.15548591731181,1.92143048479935,0.626615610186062));
#741=CARTESIAN_POINT('',(-2.15948191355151,1.90941347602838,0.626632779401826));
#742=CARTESIAN_POINT('',(-2.1674602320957,1.88517129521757,0.626655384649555));
#743=CARTESIAN_POINT('',(-2.17144141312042,1.87294574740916,0.626660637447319));
#744=CARTESIAN_POINT('',(-2.17938646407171,1.84828129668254,0.626672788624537));
#745=CARTESIAN_POINT('',(-2.18334912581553,1.8358420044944,0.626679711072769));
#746=CARTESIAN_POINT('',(-2.19121954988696,1.81085267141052,0.626706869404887));
#747=CARTESIAN_POINT('',(-2.19512675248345,1.7983024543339,0.626727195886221));
#748=CARTESIAN_POINT('',(-2.20286102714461,1.77317360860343,0.626763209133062));
#749=CARTESIAN_POINT('',(-2.20668807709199,1.76059497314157,0.626778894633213));
#750=CARTESIAN_POINT('',(-2.21423778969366,1.73549138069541,0.626800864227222));
#751=CARTESIAN_POINT('',(-2.21796095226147,1.72296657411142,0.626807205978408));
#752=CARTESIAN_POINT('',(-2.22528074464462,1.69805271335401,0.626807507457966));
#753=CARTESIAN_POINT('',(-2.22887838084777,1.68566395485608,0.626801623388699));
#754=CARTESIAN_POINT('',(-2.23592671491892,1.66110400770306,0.626779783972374));
#755=CARTESIAN_POINT('',(-2.23937890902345,1.64893324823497,0.626764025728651));
#756=CARTESIAN_POINT('',(-2.24611777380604,1.62489075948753,0.626728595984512));
#757=CARTESIAN_POINT('',(-2.24940641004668,1.61301958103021,0.626709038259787));
#758=CARTESIAN_POINT('',(-2.2558010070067,1.58965715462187,0.626678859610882));
#759=CARTESIAN_POINT('',(-2.25890939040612,1.5781665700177,0.626667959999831));
#760=CARTESIAN_POINT('',(-2.26198297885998,1.5666666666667,0.626666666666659));
#761=B_SPLINE_CURVE_WITH_KNOTS('',3,(#727,#728,#729,#730,#731,#732,#733,#734,#735,#736,#737,
#738,#739,#740,#741,#742,#743,#744,#745,#746,#747,#748,#749,#750,#751,#752,#753,#754,#755,#756,
#757,#758,#759,#760),.UNSPECIFIED.,.F.,.F.,(4,2,2,2,2,2,2,2,2,2,2,2,2,2,2,2,4),(0.,
0.0398604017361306,0.0787652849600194,0.116973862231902,0.154744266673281,0.192333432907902,
0.229996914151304,0.267988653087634,0.306560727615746,0.345726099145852,0.385158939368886,
0.424602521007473,0.46380167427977,0.502503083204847,0.540455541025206,0.577410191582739,
0.613120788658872),.UNSPECIFIED.);
#762=CARTESIAN_POINT('',(-2.26198297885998,1.5666666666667,0.62666666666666));
#763=VERTEX_POINT('',#762);
#764=EDGE_CURVE('E205',#724,#763,#761,.T.);
#765=ORIENTED_EDGE('',*,*,#764,.T.);
#766=CARTESIAN_POINT('',(-2.26198297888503,0.626666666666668,1.56666666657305));
#767=CARTESIAN_POINT('',(-2.26520019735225,0.626666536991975,1.55462889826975));
#768=CARTESIAN_POINT('',(-2.26835697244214,0.626897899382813,1.54257482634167));
#769=CARTESIAN_POINT('',(-2.27454382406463,0.627826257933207,1.51845661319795));
#770=CARTESIAN_POINT('',(-2.27757394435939,0.628523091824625,1.50639247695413));
#771=CARTESIAN_POINT('',(-2.28350314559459,0.630384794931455,1.4822714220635));
#772=CARTESIAN_POINT('',(-2.28640226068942,0.631549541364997,1.47021450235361));
#773=CARTESIAN_POINT('',(-2.2920651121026,0.634348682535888,1.44612548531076));
#774=CARTESIAN_POINT('',(-2.2948288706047,0.635983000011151,1.43409338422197));
#775=CARTESIAN_POINT('',(-2.3002166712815,0.639722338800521,1.41007177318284));
#776=CARTESIAN_POINT('',(-2.30284072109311,0.641827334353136,1.39808226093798));
#777=CARTESIAN_POINT('',(-2.30794477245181,0.646508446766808,1.37416378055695));
#778=CARTESIAN_POINT('',(-2.31042476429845,0.649084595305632,1.36223481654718));
#779=CARTESIAN_POINT('',(-2.31523635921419,0.654707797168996,1.33845553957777));
#780=CARTESIAN_POINT('',(-2.31756793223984,0.6577549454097,1.32660524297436));
#781=CARTESIAN_POINT('',(-2.32207839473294,0.664319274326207,1.30300155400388));
#782=CARTESIAN_POINT('',(-2.32425723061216,0.667836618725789,1.29124819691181));
#783=CARTESIAN_POINT('',(-2.32845717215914,0.675338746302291,1.26786005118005));
#784=CARTESIAN_POINT('',(-2.33047824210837,0.679323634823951,1.2562252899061));
#785=CARTESIAN_POINT('',(-2.33435678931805,0.687753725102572,1.23310506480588));
#786=CARTESIAN_POINT('',(-2.33621437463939,0.692198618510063,1.22161950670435));
#787=CARTESIAN_POINT('',(-2.3397634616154,0.70154347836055,1.19881668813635));
#788=CARTESIAN_POINT('',(-2.34145505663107,0.706443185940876,1.18749933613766));
#789=CARTESIAN_POINT('',(-2.34466971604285,0.716692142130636,1.16505055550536));
#790=CARTESIAN_POINT('',(-2.34619283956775,0.722041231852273,1.15391906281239));
#791=CARTESIAN_POINT('',(-2.34906816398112,0.733182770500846,1.13185950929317));
#792=CARTESIAN_POINT('',(-2.35042038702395,0.738975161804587,1.12093142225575));
#793=CARTESIAN_POINT('',(-2.3529515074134,0.750996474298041,1.09929603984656));
#794=CARTESIAN_POINT('',(-2.35413038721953,0.757225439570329,1.08858876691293));
#795=CARTESIAN_POINT('',(-2.35631242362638,0.770112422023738,1.06741220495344));
#796=CARTESIAN_POINT('',(-2.35731552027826,0.776770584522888,1.0569429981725));
#797=CARTESIAN_POINT('',(-2.35914359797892,0.79050783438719,1.03625957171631));
#798=CARTESIAN_POINT('',(-2.35996847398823,0.797587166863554,1.02604550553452));
#799=CARTESIAN_POINT('',(-2.36143767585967,0.812157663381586,1.00588959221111));
#800=CARTESIAN_POINT('',(-2.36208185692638,0.819649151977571,0.995947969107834));
#801=CARTESIAN_POINT('',(-2.36318662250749,0.835024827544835,0.976365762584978));
#802=CARTESIAN_POINT('',(-2.36364724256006,0.842908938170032,0.966725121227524));
#803=CARTESIAN_POINT('',(-2.36438476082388,0.859053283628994,0.947765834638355));
#804=CARTESIAN_POINT('',(-2.36466175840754,0.867313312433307,0.93844701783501));
#805=CARTESIAN_POINT('',(-2.36503230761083,0.884196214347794,0.920145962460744));
#806=CARTESIAN_POINT('',(-2.36512591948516,0.892818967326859,0.911163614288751));
#807=CARTESIAN_POINT('',(-2.36513000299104,0.910413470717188,0.893549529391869));
#808=CARTESIAN_POINT('',(-2.3650404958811,0.919385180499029,0.884917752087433));
#809=CARTESIAN_POINT('',(-2.36467864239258,0.937663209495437,0.868018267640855));
#810=CARTESIAN_POINT('',(-2.36440627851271,0.946969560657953,0.859750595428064));
#811=CARTESIAN_POINT('',(-2.36367900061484,0.965901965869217,0.84359218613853));
#812=CARTESIAN_POINT('',(-2.36322403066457,0.975528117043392,0.835701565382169));
#813=CARTESIAN_POINT('',(-2.36213188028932,0.995084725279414,0.820309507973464));
#814=CARTESIAN_POINT('',(-2.36149460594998,1.0050153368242,0.8128082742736));
#815=CARTESIAN_POINT('',(-2.3600380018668,1.02516488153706,0.798206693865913));
#816=CARTESIAN_POINT('',(-2.35921854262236,1.03538401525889,0.791106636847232));
#817=CARTESIAN_POINT('',(-2.35739943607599,1.05608322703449,0.777325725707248));
#818=CARTESIAN_POINT('',(-2.35639981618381,1.06656326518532,0.770644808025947));
#819=CARTESIAN_POINT('',(-2.35422388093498,1.08775998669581,0.757715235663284));
#820=CARTESIAN_POINT('',(-2.35304767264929,1.09847652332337,0.751466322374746));
#821=CARTESIAN_POINT('',(-2.35052125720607,1.12012899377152,0.739407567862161));
#822=CARTESIAN_POINT('',(-2.34917110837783,1.13106485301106,0.733597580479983));
#823=CARTESIAN_POINT('',(-2.34629960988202,1.1531386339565,0.722422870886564));
#824=CARTESIAN_POINT('',(-2.34477827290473,1.16427654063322,0.717058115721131));
#825=CARTESIAN_POINT('',(-2.34156716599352,1.18673700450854,0.706779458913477));
#826=CARTESIAN_POINT('',(-2.33987736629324,1.19805959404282,0.701865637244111));
#827=CARTESIAN_POINT('',(-2.33633210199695,1.22087195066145,0.692493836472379));
#828=CARTESIAN_POINT('',(-2.33447656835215,1.23236178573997,0.688036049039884));
#829=CARTESIAN_POINT('',(-2.33060261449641,1.25549111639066,0.679580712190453));
#830=CARTESIAN_POINT('',(-2.32858408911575,1.26713070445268,0.675583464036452));
#831=CARTESIAN_POINT('',(-2.32438689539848,1.29054183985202,0.668053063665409));
#832=CARTESIAN_POINT('',(-2.32220809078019,1.30231349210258,0.664520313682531));
#833=CARTESIAN_POINT('',(-2.31769491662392,1.32596264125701,0.657924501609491));
#834=CARTESIAN_POINT('',(-2.31536049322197,1.33784017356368,0.654861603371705));
#835=CARTESIAN_POINT('',(-2.31054161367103,1.36167732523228,0.649208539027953));
#836=CARTESIAN_POINT('',(-2.3080571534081,1.37363694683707,0.646618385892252));
#837=CARTESIAN_POINT('',(-2.30294285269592,1.39761906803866,0.641911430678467));
#838=CARTESIAN_POINT('',(-2.30031300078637,1.40964157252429,0.639794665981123));
#839=CARTESIAN_POINT('',(-2.2949126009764,1.43373037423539,0.636034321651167));
#840=CARTESIAN_POINT('',(-2.29214203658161,1.44579667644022,0.634390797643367));
#841=CARTESIAN_POINT('',(-2.28646488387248,1.46995414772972,0.631575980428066));
#842=CARTESIAN_POINT('',(-2.28355827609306,1.48204532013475,0.630404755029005));
#843=CARTESIAN_POINT('',(-2.2776137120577,1.50623376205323,0.628532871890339));
#844=CARTESIAN_POINT('',(-2.27457573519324,1.51833103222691,0.627832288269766));
#845=CARTESIAN_POINT('',(-2.26837309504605,1.5425132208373,0.6268990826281));
#846=CARTESIAN_POINT('',(-2.26520841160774,1.55459813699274,0.626666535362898));
#847=CARTESIAN_POINT('',(-2.26198297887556,1.5666666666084,0.626666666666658));
#848=B_SPLINE_CURVE_WITH_KNOTS('',3,(#766,#767,#768,#769,#770,#771,#772,#773,#774,#775,#776,
#777,#778,#779,#780,#781,#782,#783,#784,#785,#786,#787,#788,#789,#790,#791,#792,#793,#794,#795,
#796,#797,#798,#799,#800,#801,#802,#803,#804,#805,#806,#807,#808,#809,#810,#811,#812,#813,#814,
#815,#816,#817,#818,#819,#820,#821,#822,#823,#824,#825,#826,#827,#828,#829,#830,#831,#832,#833,
#834,#835,#836,#837,#838,#839,#840,#841,#842,#843,#844,#845,#846,#847),.UNSPECIFIED.,.F.,.F.,(4,
2,2,2,2,2,2,2,2,2,2,2,2,2,2,2,2,2,2,2,2,2,2,2,2,2,2,2,2,2,2,2,2,2,2,2,2,2,2,2,4),(0.,
0.0373787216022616,0.0747444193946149,0.112100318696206,0.1494500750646,0.186797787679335,
0.224148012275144,0.261505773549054,0.298876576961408,0.336255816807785,0.373610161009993,
0.410943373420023,0.44826344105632,0.485578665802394,0.522897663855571,0.560229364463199,
0.597583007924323,0.634966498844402,0.672342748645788,0.709698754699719,0.747042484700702,
0.784381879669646,0.821724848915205,0.859079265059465,0.896452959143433,0.933853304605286,
0.97124796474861,1.00862004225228,1.04597961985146,1.08333642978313,1.12069985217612,
1.15807891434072,1.195482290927,1.23291784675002,1.27036642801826,1.30781603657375,
1.34526860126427,1.38272556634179,1.42018790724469,1.45765614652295,1.49513036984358),.UNSPECIFIED.);
#849=EDGE_CURVE('E219',#71,#763,#848,.T.);
#850=ORIENTED_EDGE('',*,*,#849,.F.);
#851=EDGE_LOOP('',(#75,#114,#153,#240,#279,#318,#357,#444,#483,#522,#561,#648,#687,#726,#765,#850));
#852=FACE_BOUND('',#851,.T.);
#853=ADVANCED_FACE('F234',(#34,#852),#23,.T.);
#854=CARTESIAN_POINT('',(12.,0.,0.));
#855=DIRECTION('',(1.,0.,0.));
#856=DIRECTION('',(0.,0.,-1.));
#857=AXIS2_PLACEMENT_3D('',#854,#855,#856);
#858=CYLINDRICAL_SURFACE('',#857,4.7);
#859=CARTESIAN_POINT('',(0.,0.,0.));
#860=DIRECTION('',(1.,0.,0.));
#861=DIRECTION('',(0.,0.,-1.));
#862=AXIS2_PLACEMENT_3D('',#859,#860,#861);
#863=CIRCLE('',#862,4.7);
#864=CARTESIAN_POINT('',(0.,0.,-4.7));
#865=VERTEX_POINT('',#864);
#866=EDGE_CURVE('E245',#865,#865,#863,.T.);
#867=ORIENTED_EDGE('',*,*,#866,.F.);
#868=EDGE_LOOP('',(#867));
#869=FACE_BOUND('',#868,.T.);
#870=ORIENTED_EDGE('',*,*,#31,.T.);
#871=EDGE_LOOP('',(#870));
#872=FACE_BOUND('',#871,.T.);
#873=ADVANCED_FACE('F251',(#869,#872),#858,.T.);
#874=CARTESIAN_POINT('',(0.,4.7,0.));
#875=DIRECTION('',(-1.,0.,0.));
#876=DIRECTION('',(0.,0.,1.));
#877=AXIS2_PLACEMENT_3D('',#874,#875,#876);
#878=PLANE('',#877);
#879=CARTESIAN_POINT('',(0.,0.,0.));
#880=DIRECTION('',(1.,0.,0.));
#881=DIRECTION('',(0.,0.,-1.));
#882=AXIS2_PLACEMENT_3D('',#879,#880,#881);
#883=CIRCLE('',#882,2.);
#884=CARTESIAN_POINT('',(0.,0.,-2.));
#885=VERTEX_POINT('',#884);
#886=EDGE_CURVE('E258',#885,#885,#883,.T.);
#887=ORIENTED_EDGE('',*,*,#886,.F.);
#888=EDGE_LOOP('',(#887));
#889=FACE_BOUND('',#888,.T.);
#890=ORIENTED_EDGE('',*,*,#866,.T.);
#891=EDGE_LOOP('',(#890));
#892=FACE_BOUND('',#891,.T.);
#893=ADVANCED_FACE('F264',(#889,#892),#878,.F.);
#894=CARTESIAN_POINT('',(12.,0.,0.));
#895=DIRECTION('',(1.,0.,0.));
#896=DIRECTION('',(0.,0.,-1.));
#897=AXIS2_PLACEMENT_3D('',#894,#895,#896);
#898=CYLINDRICAL_SURFACE('',#897,2.);
#899=CARTESIAN_POINT('',(11.5705,0.,0.));
#900=DIRECTION('',(1.,0.,0.));
#901=DIRECTION('',(0.,0.,-1.));
#902=AXIS2_PLACEMENT_3D('',#899,#900,#901);
#903=CIRCLE('',#902,2.);
#904=CARTESIAN_POINT('',(11.5705,0.,-2.));
#905=VERTEX_POINT('',#904);
#906=EDGE_CURVE('E271',#905,#905,#903,.T.);
#907=ORIENTED_EDGE('',*,*,#906,.F.);
#908=EDGE_LOOP('',(#907));
#909=FACE_BOUND('',#908,.T.);
#910=ORIENTED_EDGE('',*,*,#886,.T.);
#911=EDGE_LOOP('',(#910));
#912=FACE_BOUND('',#911,.T.);
#913=ADVANCED_FACE('F277',(#909,#912),#898,.T.);
#914=CARTESIAN_POINT('',(11.5705,0.,0.));
#915=DIRECTION('',(-1.,0.,0.));
#916=DIRECTION('',(0.,0.,1.));
#917=AXIS2_PLACEMENT_3D('',#914,#915,#916);
#918=CONICAL_SURFACE('',#917,2.,0.785398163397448);
#919=CARTESIAN_POINT('',(12.,0.,0.));
#920=DIRECTION('',(1.,0.,0.));
#921=DIRECTION('',(0.,0.,-1.));
#922=AXIS2_PLACEMENT_3D('',#919,#920,#921);
#923=CIRCLE('',#922,1.5705);
#924=CARTESIAN_POINT('',(12.,0.,-1.5705));
#925=VERTEX_POINT('',#924);
#926=EDGE_CURVE('E284',#925,#925,#923,.T.);
#927=ORIENTED_EDGE('',*,*,#926,.F.);
#928=EDGE_LOOP('',(#927));
#929=FACE_BOUND('',#928,.T.);
#930=ORIENTED_EDGE('',*,*,#906,.T.);
#931=EDGE_LOOP('',(#930));
#932=FACE_BOUND('',#931,.T.);
#933=ADVANCED_FACE('F290',(#929,#932),#918,.T.);
#934=CARTESIAN_POINT('',(12.,1.5705,0.));
#935=DIRECTION('',(-1.,0.,0.));
#936=DIRECTION('',(0.,0.,1.));
#937=AXIS2_PLACEMENT_3D('',#934,#935,#936);
#938=PLANE('',#937);
#939=ORIENTED_EDGE('',*,*,#926,.T.);
#940=EDGE_LOOP('',(#939));
#941=FACE_BOUND('',#940,.T.);
#942=ADVANCED_FACE('F299',(#941),#938,.F.);
#943=CARTESIAN_POINT('',(-1.25,0.62666666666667,2.15));
#944=DIRECTION('',(0.,0.,-1.));
#945=DIRECTION('',(-1.,0.,0.));
#946=AXIS2_PLACEMENT_3D('',#943,#944,#945);
#947=PLANE('',#946);
#948=DIRECTION('',(-1.,0.,0.));
#949=VECTOR('',#948,1.);
#950=CARTESIAN_POINT('',(-1.25,0.62666666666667,2.15));
#951=LINE('',#950,#949);
#952=CARTESIAN_POINT('',(-1.25,0.62666666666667,2.15));
#953=VERTEX_POINT('',#952);
#954=EDGE_CURVE('E308',#953,#73,#951,.T.);
#955=ORIENTED_EDGE('',*,*,#954,.F.);
#956=DIRECTION('',(0.,-1.,0.));
#957=VECTOR('',#956,1.);
#958=CARTESIAN_POINT('',(-1.25,0.62666666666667,2.15));
#959=LINE('',#958,#957);
#960=CARTESIAN_POINT('',(-1.25,-0.62666666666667,2.15));
#961=VERTEX_POINT('',#960);
#962=EDGE_CURVE('E315',#953,#961,#959,.T.);
#963=ORIENTED_EDGE('',*,*,#962,.T.);
#964=DIRECTION('',(-1.,0.,0.));
#965=VECTOR('',#964,1.);
#966=CARTESIAN_POINT('',(-1.25,-0.62666666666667,2.15));
#967=LINE('',#966,#965);
#968=EDGE_CURVE('E322',#961,#112,#967,.T.);
#969=ORIENTED_EDGE('',*,*,#968,.T.);
#970=ORIENTED_EDGE('',*,*,#113,.F.);
#971=EDGE_LOOP('',(#955,#963,#969,#970));
#972=FACE_BOUND('',#971,.T.);
#973=ADVANCED_FACE('F337',(#972),#947,.T.);
#974=CARTESIAN_POINT('',(-1.25,-0.62666666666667,2.15));
#975=DIRECTION('',(0.,1.,0.));
#976=DIRECTION('',(0.,0.,1.));
#977=AXIS2_PLACEMENT_3D('',#974,#975,#976);
#978=PLANE('',#977);
#979=ORIENTED_EDGE('',*,*,#968,.F.);
#980=DIRECTION('',(0.,0.,-1.));
#981=VECTOR('',#980,1.);
#982=CARTESIAN_POINT('',(-1.25,-0.62666666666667,2.15));
#983=LINE('',#982,#981);
#984=CARTESIAN_POINT('',(-1.25,-0.62666666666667,1.5666666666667));
#985=VERTEX_POINT('',#984);
#986=EDGE_CURVE('E347',#961,#985,#983,.T.);
#987=ORIENTED_EDGE('',*,*,#986,.T.);
#988=DIRECTION('',(-1.,0.,0.));
#989=VECTOR('',#988,1.);
#990=CARTESIAN_POINT('',(-1.25,-0.62666666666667,1.5666666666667));
#991=LINE('',#990,#989);
#992=EDGE_CURVE('E354',#985,#151,#991,.T.);
#993=ORIENTED_EDGE('',*,*,#992,.T.);
#994=ORIENTED_EDGE('',*,*,#152,.F.);
#995=EDGE_LOOP('',(#979,#987,#993,#994));
#996=FACE_BOUND('',#995,.T.);
#997=ADVANCED_FACE('F369',(#996),#978,.T.);
#998=CARTESIAN_POINT('',(-1.25,-1.56666666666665,1.56666666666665));
#999=DIRECTION('',(-1.,0.,0.));
#1000=DIRECTION('',(0.,0.,1.));
#1001=AXIS2_PLACEMENT_3D('',#998,#999,#1000);
#1002=CYLINDRICAL_SURFACE('',#1001,0.939999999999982);
#1003=ORIENTED_EDGE('',*,*,#239,.T.);
#1004=ORIENTED_EDGE('',*,*,#992,.F.);
#1005=CARTESIAN_POINT('',(-1.25,-1.56666666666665,1.56666666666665));
#1006=DIRECTION('',(1.,0.,0.));
#1007=DIRECTION('',(0.,0.,-1.));
#1008=AXIS2_PLACEMENT_3D('',#1005,#1006,#1007);
#1009=CIRCLE('',#1008,0.939999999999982);
#1010=CARTESIAN_POINT('',(-1.25,-1.5666666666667,0.62666666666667));
#1011=VERTEX_POINT('',#1010);
#1012=EDGE_CURVE('E391',#1011,#985,#1009,.T.);
#1013=ORIENTED_EDGE('',*,*,#1012,.F.);
#1014=DIRECTION('',(-1.,0.,0.));
#1015=VECTOR('',#1014,1.);
#1016=CARTESIAN_POINT('',(-1.25,-1.5666666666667,0.62666666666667));
#1017=LINE('',#1016,#1015);
#1018=EDGE_CURVE('E398',#1011,#238,#1017,.T.);
#1019=ORIENTED_EDGE('',*,*,#1018,.T.);
#1020=EDGE_LOOP('',(#1003,#1004,#1013,#1019));
#1021=FACE_BOUND('',#1020,.T.);
#1022=ADVANCED_FACE('F401',(#1021),#1002,.T.);
#1023=CARTESIAN_POINT('',(-1.25,-1.5666666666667,0.62666666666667));
#1024=DIRECTION('',(0.,0.,-1.));
#1025=DIRECTION('',(-1.,0.,0.));
#1026=AXIS2_PLACEMENT_3D('',#1023,#1024,#1025);
#1027=PLANE('',#1026);
#1028=ORIENTED_EDGE('',*,*,#1018,.F.);
#1029=DIRECTION('',(0.,-1.,0.));
#1030=VECTOR('',#1029,1.);
#1031=CARTESIAN_POINT('',(-1.25,-1.5666666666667,0.62666666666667));
#1032=LINE('',#1031,#1030);
#1033=CARTESIAN_POINT('',(-1.25,-2.15,0.62666666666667));
#1034=VERTEX_POINT('',#1033);
#1035=EDGE_CURVE('E411',#1011,#1034,#1032,.T.);
#1036=ORIENTED_EDGE('',*,*,#1035,.T.);
#1037=DIRECTION('',(-1.,0.,0.));
#1038=VECTOR('',#1037,1.);
#1039=CARTESIAN_POINT('',(-1.25,-2.15,0.62666666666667));
#1040=LINE('',#1039,#1038);
#1041=EDGE_CURVE('E418',#1034,#277,#1040,.T.);
#1042=ORIENTED_EDGE('',*,*,#1041,.T.);
#1043=ORIENTED_EDGE('',*,*,#278,.F.);
#1044=EDGE_LOOP('',(#1028,#1036,#1042,#1043));
#1045=FACE_BOUND('',#1044,.T.);
#1046=ADVANCED_FACE('F433',(#1045),#1027,.T.);
#1047=CARTESIAN_POINT('',(-1.25,-2.15,0.62666666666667));
#1048=DIRECTION('',(0.,1.,0.));
#1049=DIRECTION('',(0.,0.,1.));
#1050=AXIS2_PLACEMENT_3D('',#1047,#1048,#1049);
#1051=PLANE('',#1050);
#1052=ORIENTED_EDGE('',*,*,#1041,.F.);
#1053=DIRECTION('',(0.,0.,-1.));
#1054=VECTOR('',#1053,1.);
#1055=CARTESIAN_POINT('',(-1.25,-2.15,0.62666666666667));
#1056=LINE('',#1055,#1054);
#1057=CARTESIAN_POINT('',(-1.25,-2.15,-0.62666666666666));
#1058=VERTEX_POINT('',#1057);
#1059=EDGE_CURVE('E443',#1034,#1058,#1056,.T.);
#1060=ORIENTED_EDGE('',*,*,#1059,.T.);
#1061=DIRECTION('',(-1.,0.,0.));
#1062=VECTOR('',#1061,1.);
#1063=CARTESIAN_POINT('',(-1.25,-2.15,-0.62666666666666));
#1064=LINE('',#1063,#1062);
#1065=EDGE_CURVE('E450',#1058,#316,#1064,.T.);
#1066=ORIENTED_EDGE('',*,*,#1065,.T.);
#1067=ORIENTED_EDGE('',*,*,#317,.F.);
#1068=EDGE_LOOP('',(#1052,#1060,#1066,#1067));
#1069=FACE_BOUND('',#1068,.T.);
#1070=ADVANCED_FACE('F465',(#1069),#1051,.T.);
#1071=CARTESIAN_POINT('',(-1.25,-2.15,-0.62666666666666));
#1072=DIRECTION('',(0.,0.,1.));
#1073=DIRECTION('',(1.,0.,0.));
#1074=AXIS2_PLACEMENT_3D('',#1071,#1072,#1073);
#1075=PLANE('',#1074);
#1076=ORIENTED_EDGE('',*,*,#1065,.F.);
#1077=DIRECTION('',(0.,1.,0.));
#1078=VECTOR('',#1077,1.);
#1079=CARTESIAN_POINT('',(-1.25,-2.15,-0.62666666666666));
#1080=LINE('',#1079,#1078);
#1081=CARTESIAN_POINT('',(-1.25,-1.5666666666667,-0.62666666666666));
#1082=VERTEX_POINT('',#1081);
#1083=EDGE_CURVE('E475',#1058,#1082,#1080,.T.);
#1084=ORIENTED_EDGE('',*,*,#1083,.T.);
#1085=DIRECTION('',(-1.,0.,0.));
#1086=VECTOR('',#1085,1.);
#1087=CARTESIAN_POINT('',(-1.25,-1.5666666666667,-0.62666666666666));
#1088=LINE('',#1087,#1086);
#1089=EDGE_CURVE('E482',#1082,#355,#1088,.T.);
#1090=ORIENTED_EDGE('',*,*,#1089,.T.);
#1091=ORIENTED_EDGE('',*,*,#356,.F.);
#1092=EDGE_LOOP('',(#1076,#1084,#1090,#1091));
#1093=FACE_BOUND('',#1092,.T.);
#1094=ADVANCED_FACE('F497',(#1093),#1075,.T.);
#1095=CARTESIAN_POINT('',(-1.25,-1.56666666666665,-1.56666666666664));
#1096=DIRECTION('',(-1.,0.,0.));
#1097=DIRECTION('',(0.,0.,1.));
#1098=AXIS2_PLACEMENT_3D('',#1095,#1096,#1097);
#1099=CYLINDRICAL_SURFACE('',#1098,0.939999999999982);
#1100=ORIENTED_EDGE('',*,*,#443,.T.);
#1101=ORIENTED_EDGE('',*,*,#1089,.F.);
#1102=CARTESIAN_POINT('',(-1.25,-1.56666666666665,-1.56666666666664));
#1103=DIRECTION('',(1.,0.,0.));
#1104=DIRECTION('',(0.,1.,0.));
#1105=AXIS2_PLACEMENT_3D('',#1102,#1103,#1104);
#1106=CIRCLE('',#1105,0.939999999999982);
#1107=CARTESIAN_POINT('',(-1.25,-0.62666666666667,-1.5666666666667));
#1108=VERTEX_POINT('',#1107);
#1109=EDGE_CURVE('E519',#1108,#1082,#1106,.T.);
#1110=ORIENTED_EDGE('',*,*,#1109,.F.);
#1111=DIRECTION('',(-1.,0.,0.));
#1112=VECTOR('',#1111,1.);
#1113=CARTESIAN_POINT('',(-1.25,-0.62666666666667,-1.5666666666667));
#1114=LINE('',#1113,#1112);
#1115=EDGE_CURVE('E526',#1108,#442,#1114,.T.);
#1116=ORIENTED_EDGE('',*,*,#1115,.T.);
#1117=EDGE_LOOP('',(#1100,#1101,#1110,#1116));
#1118=FACE_BOUND('',#1117,.T.);
#1119=ADVANCED_FACE('F529',(#1118),#1099,.T.);
#1120=CARTESIAN_POINT('',(-1.25,-0.62666666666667,-1.5666666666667));
#1121=DIRECTION('',(0.,1.,0.));
#1122=DIRECTION('',(0.,0.,1.));
#1123=AXIS2_PLACEMENT_3D('',#1120,#1121,#1122);
#1124=PLANE('',#1123);
#1125=ORIENTED_EDGE('',*,*,#1115,.F.);
#1126=DIRECTION('',(0.,0.,-1.));
#1127=VECTOR('',#1126,1.);
#1128=CARTESIAN_POINT('',(-1.25,-0.62666666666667,-1.5666666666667));
#1129=LINE('',#1128,#1127);
#1130=CARTESIAN_POINT('',(-1.25,-0.62666666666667,-2.15));
#1131=VERTEX_POINT('',#1130);
#1132=EDGE_CURVE('E539',#1108,#1131,#1129,.T.);
#1133=ORIENTED_EDGE('',*,*,#1132,.T.);
#1134=DIRECTION('',(-1.,0.,0.));
#1135=VECTOR('',#1134,1.);
#1136=CARTESIAN_POINT('',(-1.25,-0.62666666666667,-2.15));
#1137=LINE('',#1136,#1135);
#1138=EDGE_CURVE('E546',#1131,#481,#1137,.T.);
#1139=ORIENTED_EDGE('',*,*,#1138,.T.);
#1140=ORIENTED_EDGE('',*,*,#482,.F.);
#1141=EDGE_LOOP('',(#1125,#1133,#1139,#1140));
#1142=FACE_BOUND('',#1141,.T.);
#1143=ADVANCED_FACE('F561',(#1142),#1124,.T.);
#1144=CARTESIAN_POINT('',(-1.25,-0.62666666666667,-2.15));
#1145=DIRECTION('',(0.,0.,1.));
#1146=DIRECTION('',(1.,0.,0.));
#1147=AXIS2_PLACEMENT_3D('',#1144,#1145,#1146);
#1148=PLANE('',#1147);
#1149=ORIENTED_EDGE('',*,*,#1138,.F.);
#1150=DIRECTION('',(0.,1.,0.));
#1151=VECTOR('',#1150,1.);
#1152=CARTESIAN_POINT('',(-1.25,-0.62666666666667,-2.15));
#1153=LINE('',#1152,#1151);
#1154=CARTESIAN_POINT('',(-1.25,0.62666666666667,-2.15));
#1155=VERTEX_POINT('',#1154);
#1156=EDGE_CURVE('E571',#1131,#1155,#1153,.T.);
#1157=ORIENTED_EDGE('',*,*,#1156,.T.);
#1158=DIRECTION('',(-1.,0.,0.));
#1159=VECTOR('',#1158,1.);
#1160=CARTESIAN_POINT('',(-1.25,0.62666666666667,-2.15));
#1161=LINE('',#1160,#1159);
#1162=EDGE_CURVE('E578',#1155,#520,#1161,.T.);
#1163=ORIENTED_EDGE('',*,*,#1162,.T.);
#1164=ORIENTED_EDGE('',*,*,#521,.F.);
#1165=EDGE_LOOP('',(#1149,#1157,#1163,#1164));
#1166=FACE_BOUND('',#1165,.T.);
#1167=ADVANCED_FACE('F593',(#1166),#1148,.T.);
#1168=CARTESIAN_POINT('',(-1.25,0.62666666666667,-2.15));
#1169=DIRECTION('',(0.,-1.,0.));
#1170=DIRECTION('',(0.,0.,-1.));
#1171=AXIS2_PLACEMENT_3D('',#1168,#1169,#1170);
#1172=PLANE('',#1171);
#1173=ORIENTED_EDGE('',*,*,#1162,.F.);
#1174=DIRECTION('',(0.,0.,1.));
#1175=VECTOR('',#1174,1.);
#1176=CARTESIAN_POINT('',(-1.25,0.62666666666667,-2.15));
#1177=LINE('',#1176,#1175);
#1178=CARTESIAN_POINT('',(-1.25,0.62666666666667,-1.5666666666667));
#1179=VERTEX_POINT('',#1178);
#1180=EDGE_CURVE('E603',#1155,#1179,#1177,.T.);
#1181=ORIENTED_EDGE('',*,*,#1180,.T.);
#1182=DIRECTION('',(-1.,0.,0.));
#1183=VECTOR('',#1182,1.);
#1184=CARTESIAN_POINT('',(-1.25,0.62666666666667,-1.5666666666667));
#1185=LINE('',#1184,#1183);
#1186=EDGE_CURVE('E610',#1179,#559,#1185,.T.);
#1187=ORIENTED_EDGE('',*,*,#1186,.T.);
#1188=ORIENTED_EDGE('',*,*,#560,.F.);
#1189=EDGE_LOOP('',(#1173,#1181,#1187,#1188));
#1190=FACE_BOUND('',#1189,.T.);
#1191=ADVANCED_FACE('F625',(#1190),#1172,.T.);
#1192=CARTESIAN_POINT('',(-1.25,1.56666666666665,-1.56666666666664));
#1193=DIRECTION('',(-1.,0.,0.));
#1194=DIRECTION('',(0.,0.,1.));
#1195=AXIS2_PLACEMENT_3D('',#1192,#1193,#1194);
#1196=CYLINDRICAL_SURFACE('',#1195,0.939999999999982);
#1197=ORIENTED_EDGE('',*,*,#647,.T.);
#1198=ORIENTED_EDGE('',*,*,#1186,.F.);
#1199=CARTESIAN_POINT('',(-1.25,1.56666666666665,-1.56666666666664));
#1200=DIRECTION('',(1.,0.,0.));
#1201=DIRECTION('',(0.,0.,1.));
#1202=AXIS2_PLACEMENT_3D('',#1199,#1200,#1201);
#1203=CIRCLE('',#1202,0.939999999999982);
#1204=CARTESIAN_POINT('',(-1.25,1.5666666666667,-0.62666666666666));
#1205=VERTEX_POINT('',#1204);
#1206=EDGE_CURVE('E647',#1205,#1179,#1203,.T.);
#1207=ORIENTED_EDGE('',*,*,#1206,.F.);
#1208=DIRECTION('',(-1.,0.,0.));
#1209=VECTOR('',#1208,1.);
#1210=CARTESIAN_POINT('',(-1.25,1.5666666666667,-0.62666666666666));
#1211=LINE('',#1210,#1209);
#1212=EDGE_CURVE('E654',#1205,#646,#1211,.T.);
#1213=ORIENTED_EDGE('',*,*,#1212,.T.);
#1214=EDGE_LOOP('',(#1197,#1198,#1207,#1213));
#1215=FACE_BOUND('',#1214,.T.);
#1216=ADVANCED_FACE('F657',(#1215),#1196,.T.);
#1217=CARTESIAN_POINT('',(-1.25,1.5666666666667,-0.62666666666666));
#1218=DIRECTION('',(0.,0.,1.));
#1219=DIRECTION('',(1.,0.,0.));
#1220=AXIS2_PLACEMENT_3D('',#1217,#1218,#1219);
#1221=PLANE('',#1220);
#1222=ORIENTED_EDGE('',*,*,#1212,.F.);
#1223=DIRECTION('',(0.,1.,0.));
#1224=VECTOR('',#1223,1.);
#1225=CARTESIAN_POINT('',(-1.25,1.5666666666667,-0.62666666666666));
#1226=LINE('',#1225,#1224);
#1227=CARTESIAN_POINT('',(-1.25,2.15,-0.62666666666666));
#1228=VERTEX_POINT('',#1227);
#1229=EDGE_CURVE('E667',#1205,#1228,#1226,.T.);
#1230=ORIENTED_EDGE('',*,*,#1229,.T.);
#1231=DIRECTION('',(-1.,0.,0.));
#1232=VECTOR('',#1231,1.);
#1233=CARTESIAN_POINT('',(-1.25,2.15,-0.62666666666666));
#1234=LINE('',#1233,#1232);
#1235=EDGE_CURVE('E674',#1228,#685,#1234,.T.);
#1236=ORIENTED_EDGE('',*,*,#1235,.T.);
#1237=ORIENTED_EDGE('',*,*,#686,.F.);
#1238=EDGE_LOOP('',(#1222,#1230,#1236,#1237));
#1239=FACE_BOUND('',#1238,.T.);
#1240=ADVANCED_FACE('F689',(#1239),#1221,.T.);
#1241=CARTESIAN_POINT('',(-1.25,2.15,-0.62666666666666));
#1242=DIRECTION('',(0.,-1.,0.));
#1243=DIRECTION('',(0.,0.,-1.));
#1244=AXIS2_PLACEMENT_3D('',#1241,#1242,#1243);
#1245=PLANE('',#1244);
#1246=ORIENTED_EDGE('',*,*,#1235,.F.);
#1247=DIRECTION('',(0.,0.,1.));
#1248=VECTOR('',#1247,1.);
#1249=CARTESIAN_POINT('',(-1.25,2.15,-0.62666666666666));
#1250=LINE('',#1249,#1248);
#1251=CARTESIAN_POINT('',(-1.25,2.15,0.62666666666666));
#1252=VERTEX_POINT('',#1251);
#1253=EDGE_CURVE('E699',#1228,#1252,#1250,.T.);
#1254=ORIENTED_EDGE('',*,*,#1253,.T.);
#1255=DIRECTION('',(-1.,0.,0.));
#1256=VECTOR('',#1255,1.);
#1257=CARTESIAN_POINT('',(-1.25,2.15,0.62666666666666));
#1258=LINE('',#1257,#1256);
#1259=EDGE_CURVE('E706',#1252,#724,#1258,.T.);
#1260=ORIENTED_EDGE('',*,*,#1259,.T.);
#1261=ORIENTED_EDGE('',*,*,#725,.F.);
#1262=EDGE_LOOP('',(#1246,#1254,#1260,#1261));
#1263=FACE_BOUND('',#1262,.T.);
#1264=ADVANCED_FACE('F721',(#1263),#1245,.T.);
#1265=CARTESIAN_POINT('',(-1.25,2.15,0.62666666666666));
#1266=DIRECTION('',(0.,0.,-1.));
#1267=DIRECTION('',(-1.,0.,0.));
#1268=AXIS2_PLACEMENT_3D('',#1265,#1266,#1267);
#1269=PLANE('',#1268);
#1270=ORIENTED_EDGE('',*,*,#1259,.F.);
#1271=DIRECTION('',(0.,-1.,0.));
#1272=VECTOR('',#1271,1.);
#1273=CARTESIAN_POINT('',(-1.25,2.15,0.62666666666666));
#1274=LINE('',#1273,#1272);
#1275=CARTESIAN_POINT('',(-1.25,1.5666666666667,0.62666666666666));
#1276=VERTEX_POINT('',#1275);
#1277=EDGE_CURVE('E731',#1252,#1276,#1274,.T.);
#1278=ORIENTED_EDGE('',*,*,#1277,.T.);
#1279=DIRECTION('',(-1.,0.,0.));
#1280=VECTOR('',#1279,1.);
#1281=CARTESIAN_POINT('',(-1.25,1.5666666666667,0.62666666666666));
#1282=LINE('',#1281,#1280);
#1283=EDGE_CURVE('E738',#1276,#763,#1282,.T.);
#1284=ORIENTED_EDGE('',*,*,#1283,.T.);
#1285=ORIENTED_EDGE('',*,*,#764,.F.);
#1286=EDGE_LOOP('',(#1270,#1278,#1284,#1285));
#1287=FACE_BOUND('',#1286,.T.);
#1288=ADVANCED_FACE('F753',(#1287),#1269,.T.);
#1289=CARTESIAN_POINT('',(-1.25,1.56666666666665,1.56666666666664));
#1290=DIRECTION('',(-1.,0.,0.));
#1291=DIRECTION('',(0.,0.,1.));
#1292=AXIS2_PLACEMENT_3D('',#1289,#1290,#1291);
#1293=CYLINDRICAL_SURFACE('',#1292,0.939999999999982);
#1294=ORIENTED_EDGE('',*,*,#849,.T.);
#1295=ORIENTED_EDGE('',*,*,#1283,.F.);
#1296=CARTESIAN_POINT('',(-1.25,1.56666666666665,1.56666666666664));
#1297=DIRECTION('',(1.,0.,0.));
#1298=DIRECTION('',(0.,-1.,0.));
#1299=AXIS2_PLACEMENT_3D('',#1296,#1297,#1298);
#1300=CIRCLE('',#1299,0.939999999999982);
#1301=CARTESIAN_POINT('',(-1.25,0.62666666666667,1.5666666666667));
#1302=VERTEX_POINT('',#1301);
#1303=EDGE_CURVE('E775',#1302,#1276,#1300,.T.);
#1304=ORIENTED_EDGE('',*,*,#1303,.F.);
#1305=DIRECTION('',(-1.,0.,0.));
#1306=VECTOR('',#1305,1.);
#1307=CARTESIAN_POINT('',(-1.25,0.62666666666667,1.5666666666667));
#1308=LINE('',#1307,#1306);
#1309=EDGE_CURVE('E782',#1302,#71,#1308,.T.);
#1310=ORIENTED_EDGE('',*,*,#1309,.T.);
#1311=EDGE_LOOP('',(#1294,#1295,#1304,#1310));
#1312=FACE_BOUND('',#1311,.T.);
#1313=ADVANCED_FACE('F785',(#1312),#1293,.T.);
#1314=CARTESIAN_POINT('',(-1.25,0.62666666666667,1.5666666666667));
#1315=DIRECTION('',(0.,-1.,0.));
#1316=DIRECTION('',(0.,0.,-1.));
#1317=AXIS2_PLACEMENT_3D('',#1314,#1315,#1316);
#1318=PLANE('',#1317);
#1319=ORIENTED_EDGE('',*,*,#1309,.F.);
#1320=DIRECTION('',(0.,0.,1.));
#1321=VECTOR('',#1320,1.);
#1322=CARTESIAN_POINT('',(-1.25,0.62666666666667,1.5666666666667));
#1323=LINE('',#1322,#1321);
#1324=EDGE_CURVE('E795',#1302,#953,#1323,.T.);
#1325=ORIENTED_EDGE('',*,*,#1324,.T.);
#1326=ORIENTED_EDGE('',*,*,#954,.T.);
#1327=ORIENTED_EDGE('',*,*,#74,.F.);
#1328=EDGE_LOOP('',(#1319,#1325,#1326,#1327));
#1329=FACE_BOUND('',#1328,.T.);
#1330=ADVANCED_FACE('F811',(#1329),#1318,.T.);
#1331=CARTESIAN_POINT('',(-1.25,-1.56666666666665,1.56666666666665));
#1332=DIRECTION('',(1.,0.,0.));
#1333=DIRECTION('',(0.,0.,-1.));
#1334=AXIS2_PLACEMENT_3D('',#1331,#1332,#1333);
#1335=PLANE('',#1334);
#1336=ORIENTED_EDGE('',*,*,#962,.F.);
#1337=ORIENTED_EDGE('',*,*,#1324,.F.);
#1338=ORIENTED_EDGE('',*,*,#1303,.T.);
#1339=ORIENTED_EDGE('',*,*,#1277,.F.);
#1340=ORIENTED_EDGE('',*,*,#1253,.F.);
#1341=ORIENTED_EDGE('',*,*,#1229,.F.);
#1342=ORIENTED_EDGE('',*,*,#1206,.T.);
#1343=ORIENTED_EDGE('',*,*,#1180,.F.);
#1344=ORIENTED_EDGE('',*,*,#1156,.F.);
#1345=ORIENTED_EDGE('',*,*,#1132,.F.);
#1346=ORIENTED_EDGE('',*,*,#1109,.T.);
#1347=ORIENTED_EDGE('',*,*,#1083,.F.);
#1348=ORIENTED_EDGE('',*,*,#1059,.F.);
#1349=ORIENTED_EDGE('',*,*,#1035,.F.);
#1350=ORIENTED_EDGE('',*,*,#1012,.T.);
#1351=ORIENTED_EDGE('',*,*,#986,.F.);
#1352=EDGE_LOOP('',(#1336,#1337,#1338,#1339,#1340,#1341,#1342,#1343,#1344,#1345,#1346,#1347,
#1348,#1349,#1350,#1351));
#1353=FACE_BOUND('',#1352,.T.);
#1354=ADVANCED_FACE('F835',(#1353),#1335,.F.);
#1355=CLOSED_SHELL('',(#853,#873,#893,#913,#933,#942,#973,#997,#1022,#1046,#1070,#1094,#1119,
#1143,#1167,#1191,#1216,#1240,#1264,#1288,#1313,#1330,#1354));
#1356=MANIFOLD_SOLID_BREP('B1',#1355);
#1357=ADVANCED_BREP_SHAPE_REPRESENTATION('',(#18,#1356),#14);
#1358=SHAPE_DEFINITION_REPRESENTATION(#9,#1357);
ENDSEC;
END-ISO-10303-21;
